VERSION 5.8 ;
BUSBITCHARS "[]" ;
DIVIDERCHAR "/" ;
UNITS
    DATABASE MICRONS 1000 ;
END UNITS

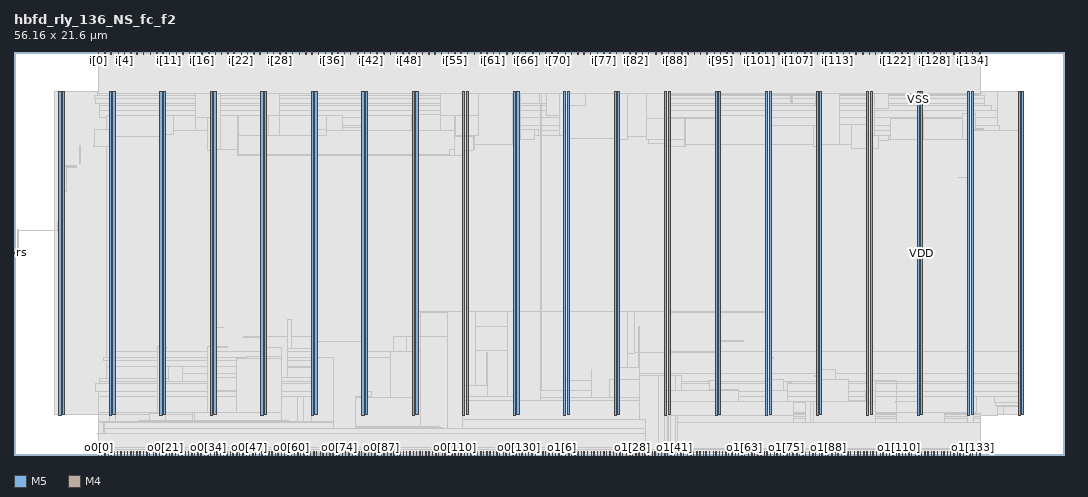
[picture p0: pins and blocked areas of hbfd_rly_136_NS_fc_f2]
MACRO hbfd_rly_136_NS_fc_f2
  FOREIGN hbfd_rly_136_NS_fc_f2 0 0 ;
  CLASS BLOCK ;
  SIZE 56.16 BY 21.6 ;
  PIN clk_in
    DIRECTION INPUT ;
    USE SIGNAL ;
    PORT
      LAYER M5 ;
        RECT  28.08 21.408 28.104 21.6 ;
    END
  END clk_in
  PIN clk_out0
    DIRECTION OUTPUT ;
    USE SIGNAL ;
    PORT
      LAYER M5 ;
        RECT  16.176 0 16.2 0.192 ;
    END
  END clk_out0
  PIN clk_out1
    DIRECTION OUTPUT ;
    USE SIGNAL ;
    PORT
      LAYER M5 ;
        RECT  39.936 0 39.96 0.192 ;
    END
  END clk_out1
  PIN i[0]
    DIRECTION INPUT ;
    USE SIGNAL ;
    PORT
      LAYER M5 ;
        RECT  4.512 21.408 4.536 21.6 ;
    END
  END i[0]
  PIN i[100]
    DIRECTION INPUT ;
    USE SIGNAL ;
    PORT
      LAYER M5 ;
        RECT  39.504 21.408 39.528 21.6 ;
    END
  END i[100]
  PIN i[101]
    DIRECTION INPUT ;
    USE SIGNAL ;
    PORT
      LAYER M5 ;
        RECT  39.84 21.408 39.864 21.6 ;
    END
  END i[101]
  PIN i[102]
    DIRECTION INPUT ;
    USE SIGNAL ;
    PORT
      LAYER M5 ;
        RECT  40.176 21.408 40.2 21.6 ;
    END
  END i[102]
  PIN i[103]
    DIRECTION INPUT ;
    USE SIGNAL ;
    PORT
      LAYER M5 ;
        RECT  40.56 21.408 40.584 21.6 ;
    END
  END i[103]
  PIN i[104]
    DIRECTION INPUT ;
    USE SIGNAL ;
    PORT
      LAYER M5 ;
        RECT  40.896 21.408 40.92 21.6 ;
    END
  END i[104]
  PIN i[105]
    DIRECTION INPUT ;
    USE SIGNAL ;
    PORT
      LAYER M5 ;
        RECT  41.232 21.408 41.256 21.6 ;
    END
  END i[105]
  PIN i[106]
    DIRECTION INPUT ;
    USE SIGNAL ;
    PORT
      LAYER M5 ;
        RECT  41.568 21.408 41.592 21.6 ;
    END
  END i[106]
  PIN i[107]
    DIRECTION INPUT ;
    USE SIGNAL ;
    PORT
      LAYER M5 ;
        RECT  41.904 21.408 41.928 21.6 ;
    END
  END i[107]
  PIN i[108]
    DIRECTION INPUT ;
    USE SIGNAL ;
    PORT
      LAYER M5 ;
        RECT  42.288 21.408 42.312 21.6 ;
    END
  END i[108]
  PIN i[109]
    DIRECTION INPUT ;
    USE SIGNAL ;
    PORT
      LAYER M5 ;
        RECT  42.624 21.408 42.648 21.6 ;
    END
  END i[109]
  PIN i[10]
    DIRECTION INPUT ;
    USE SIGNAL ;
    PORT
      LAYER M5 ;
        RECT  7.968 21.408 7.992 21.6 ;
    END
  END i[10]
  PIN i[110]
    DIRECTION INPUT ;
    USE SIGNAL ;
    PORT
      LAYER M5 ;
        RECT  42.96 21.408 42.984 21.6 ;
    END
  END i[110]
  PIN i[111]
    DIRECTION INPUT ;
    USE SIGNAL ;
    PORT
      LAYER M5 ;
        RECT  43.296 21.408 43.32 21.6 ;
    END
  END i[111]
  PIN i[112]
    DIRECTION INPUT ;
    USE SIGNAL ;
    PORT
      LAYER M5 ;
        RECT  43.68 21.408 43.704 21.6 ;
    END
  END i[112]
  PIN i[113]
    DIRECTION INPUT ;
    USE SIGNAL ;
    PORT
      LAYER M5 ;
        RECT  44.016 21.408 44.04 21.6 ;
    END
  END i[113]
  PIN i[114]
    DIRECTION INPUT ;
    USE SIGNAL ;
    PORT
      LAYER M5 ;
        RECT  44.352 21.408 44.376 21.6 ;
    END
  END i[114]
  PIN i[115]
    DIRECTION INPUT ;
    USE SIGNAL ;
    PORT
      LAYER M5 ;
        RECT  44.688 21.408 44.712 21.6 ;
    END
  END i[115]
  PIN i[116]
    DIRECTION INPUT ;
    USE SIGNAL ;
    PORT
      LAYER M5 ;
        RECT  45.024 21.408 45.048 21.6 ;
    END
  END i[116]
  PIN i[117]
    DIRECTION INPUT ;
    USE SIGNAL ;
    PORT
      LAYER M5 ;
        RECT  45.408 21.408 45.432 21.6 ;
    END
  END i[117]
  PIN i[118]
    DIRECTION INPUT ;
    USE SIGNAL ;
    PORT
      LAYER M5 ;
        RECT  45.744 21.408 45.768 21.6 ;
    END
  END i[118]
  PIN i[119]
    DIRECTION INPUT ;
    USE SIGNAL ;
    PORT
      LAYER M5 ;
        RECT  46.08 21.408 46.104 21.6 ;
    END
  END i[119]
  PIN i[11]
    DIRECTION INPUT ;
    USE SIGNAL ;
    PORT
      LAYER M5 ;
        RECT  8.304 21.408 8.328 21.6 ;
    END
  END i[11]
  PIN i[120]
    DIRECTION INPUT ;
    USE SIGNAL ;
    PORT
      LAYER M5 ;
        RECT  46.416 21.408 46.44 21.6 ;
    END
  END i[120]
  PIN i[121]
    DIRECTION INPUT ;
    USE SIGNAL ;
    PORT
      LAYER M5 ;
        RECT  46.8 21.408 46.824 21.6 ;
    END
  END i[121]
  PIN i[122]
    DIRECTION INPUT ;
    USE SIGNAL ;
    PORT
      LAYER M5 ;
        RECT  47.136 21.408 47.16 21.6 ;
    END
  END i[122]
  PIN i[123]
    DIRECTION INPUT ;
    USE SIGNAL ;
    PORT
      LAYER M5 ;
        RECT  47.472 21.408 47.496 21.6 ;
    END
  END i[123]
  PIN i[124]
    DIRECTION INPUT ;
    USE SIGNAL ;
    PORT
      LAYER M5 ;
        RECT  47.808 21.408 47.832 21.6 ;
    END
  END i[124]
  PIN i[125]
    DIRECTION INPUT ;
    USE SIGNAL ;
    PORT
      LAYER M5 ;
        RECT  48.144 21.408 48.168 21.6 ;
    END
  END i[125]
  PIN i[126]
    DIRECTION INPUT ;
    USE SIGNAL ;
    PORT
      LAYER M5 ;
        RECT  48.528 21.408 48.552 21.6 ;
    END
  END i[126]
  PIN i[127]
    DIRECTION INPUT ;
    USE SIGNAL ;
    PORT
      LAYER M5 ;
        RECT  48.864 21.408 48.888 21.6 ;
    END
  END i[127]
  PIN i[128]
    DIRECTION INPUT ;
    USE SIGNAL ;
    PORT
      LAYER M5 ;
        RECT  49.2 21.408 49.224 21.6 ;
    END
  END i[128]
  PIN i[129]
    DIRECTION INPUT ;
    USE SIGNAL ;
    PORT
      LAYER M5 ;
        RECT  49.536 21.408 49.56 21.6 ;
    END
  END i[129]
  PIN i[12]
    DIRECTION INPUT ;
    USE SIGNAL ;
    PORT
      LAYER M5 ;
        RECT  8.688 21.408 8.712 21.6 ;
    END
  END i[12]
  PIN i[130]
    DIRECTION INPUT ;
    USE SIGNAL ;
    PORT
      LAYER M5 ;
        RECT  49.872 21.408 49.896 21.6 ;
    END
  END i[130]
  PIN i[131]
    DIRECTION INPUT ;
    USE SIGNAL ;
    PORT
      LAYER M5 ;
        RECT  50.256 21.408 50.28 21.6 ;
    END
  END i[131]
  PIN i[132]
    DIRECTION INPUT ;
    USE SIGNAL ;
    PORT
      LAYER M5 ;
        RECT  50.592 21.408 50.616 21.6 ;
    END
  END i[132]
  PIN i[133]
    DIRECTION INPUT ;
    USE SIGNAL ;
    PORT
      LAYER M5 ;
        RECT  50.928 21.408 50.952 21.6 ;
    END
  END i[133]
  PIN i[134]
    DIRECTION INPUT ;
    USE SIGNAL ;
    PORT
      LAYER M5 ;
        RECT  51.264 21.408 51.288 21.6 ;
    END
  END i[134]
  PIN i[135]
    DIRECTION INPUT ;
    USE SIGNAL ;
    PORT
      LAYER M5 ;
        RECT  51.648 21.408 51.672 21.6 ;
    END
  END i[135]
  PIN i[13]
    DIRECTION INPUT ;
    USE SIGNAL ;
    PORT
      LAYER M5 ;
        RECT  9.024 21.408 9.048 21.6 ;
    END
  END i[13]
  PIN i[14]
    DIRECTION INPUT ;
    USE SIGNAL ;
    PORT
      LAYER M5 ;
        RECT  9.36 21.408 9.384 21.6 ;
    END
  END i[14]
  PIN i[15]
    DIRECTION INPUT ;
    USE SIGNAL ;
    PORT
      LAYER M5 ;
        RECT  9.696 21.408 9.72 21.6 ;
    END
  END i[15]
  PIN i[16]
    DIRECTION INPUT ;
    USE SIGNAL ;
    PORT
      LAYER M5 ;
        RECT  10.032 21.408 10.056 21.6 ;
    END
  END i[16]
  PIN i[17]
    DIRECTION INPUT ;
    USE SIGNAL ;
    PORT
      LAYER M5 ;
        RECT  10.416 21.408 10.44 21.6 ;
    END
  END i[17]
  PIN i[18]
    DIRECTION INPUT ;
    USE SIGNAL ;
    PORT
      LAYER M5 ;
        RECT  10.752 21.408 10.776 21.6 ;
    END
  END i[18]
  PIN i[19]
    DIRECTION INPUT ;
    USE SIGNAL ;
    PORT
      LAYER M5 ;
        RECT  11.088 21.408 11.112 21.6 ;
    END
  END i[19]
  PIN i[1]
    DIRECTION INPUT ;
    USE SIGNAL ;
    PORT
      LAYER M5 ;
        RECT  4.848 21.408 4.872 21.6 ;
    END
  END i[1]
  PIN i[20]
    DIRECTION INPUT ;
    USE SIGNAL ;
    PORT
      LAYER M5 ;
        RECT  11.424 21.408 11.448 21.6 ;
    END
  END i[20]
  PIN i[21]
    DIRECTION INPUT ;
    USE SIGNAL ;
    PORT
      LAYER M5 ;
        RECT  11.76 21.408 11.784 21.6 ;
    END
  END i[21]
  PIN i[22]
    DIRECTION INPUT ;
    USE SIGNAL ;
    PORT
      LAYER M5 ;
        RECT  12.144 21.408 12.168 21.6 ;
    END
  END i[22]
  PIN i[23]
    DIRECTION INPUT ;
    USE SIGNAL ;
    PORT
      LAYER M5 ;
        RECT  12.48 21.408 12.504 21.6 ;
    END
  END i[23]
  PIN i[24]
    DIRECTION INPUT ;
    USE SIGNAL ;
    PORT
      LAYER M5 ;
        RECT  12.816 21.408 12.84 21.6 ;
    END
  END i[24]
  PIN i[25]
    DIRECTION INPUT ;
    USE SIGNAL ;
    PORT
      LAYER M5 ;
        RECT  13.152 21.408 13.176 21.6 ;
    END
  END i[25]
  PIN i[26]
    DIRECTION INPUT ;
    USE SIGNAL ;
    PORT
      LAYER M5 ;
        RECT  13.536 21.408 13.56 21.6 ;
    END
  END i[26]
  PIN i[27]
    DIRECTION INPUT ;
    USE SIGNAL ;
    PORT
      LAYER M5 ;
        RECT  13.872 21.408 13.896 21.6 ;
    END
  END i[27]
  PIN i[28]
    DIRECTION INPUT ;
    USE SIGNAL ;
    PORT
      LAYER M5 ;
        RECT  14.208 21.408 14.232 21.6 ;
    END
  END i[28]
  PIN i[29]
    DIRECTION INPUT ;
    USE SIGNAL ;
    PORT
      LAYER M5 ;
        RECT  14.544 21.408 14.568 21.6 ;
    END
  END i[29]
  PIN i[2]
    DIRECTION INPUT ;
    USE SIGNAL ;
    PORT
      LAYER M5 ;
        RECT  5.184 21.408 5.208 21.6 ;
    END
  END i[2]
  PIN i[30]
    DIRECTION INPUT ;
    USE SIGNAL ;
    PORT
      LAYER M5 ;
        RECT  14.88 21.408 14.904 21.6 ;
    END
  END i[30]
  PIN i[31]
    DIRECTION INPUT ;
    USE SIGNAL ;
    PORT
      LAYER M5 ;
        RECT  15.264 21.408 15.288 21.6 ;
    END
  END i[31]
  PIN i[32]
    DIRECTION INPUT ;
    USE SIGNAL ;
    PORT
      LAYER M5 ;
        RECT  15.6 21.408 15.624 21.6 ;
    END
  END i[32]
  PIN i[33]
    DIRECTION INPUT ;
    USE SIGNAL ;
    PORT
      LAYER M5 ;
        RECT  15.936 21.408 15.96 21.6 ;
    END
  END i[33]
  PIN i[34]
    DIRECTION INPUT ;
    USE SIGNAL ;
    PORT
      LAYER M5 ;
        RECT  16.272 21.408 16.296 21.6 ;
    END
  END i[34]
  PIN i[35]
    DIRECTION INPUT ;
    USE SIGNAL ;
    PORT
      LAYER M5 ;
        RECT  16.656 21.408 16.68 21.6 ;
    END
  END i[35]
  PIN i[36]
    DIRECTION INPUT ;
    USE SIGNAL ;
    PORT
      LAYER M5 ;
        RECT  16.992 21.408 17.016 21.6 ;
    END
  END i[36]
  PIN i[37]
    DIRECTION INPUT ;
    USE SIGNAL ;
    PORT
      LAYER M5 ;
        RECT  17.328 21.408 17.352 21.6 ;
    END
  END i[37]
  PIN i[38]
    DIRECTION INPUT ;
    USE SIGNAL ;
    PORT
      LAYER M5 ;
        RECT  17.664 21.408 17.688 21.6 ;
    END
  END i[38]
  PIN i[39]
    DIRECTION INPUT ;
    USE SIGNAL ;
    PORT
      LAYER M5 ;
        RECT  18 21.408 18.024 21.6 ;
    END
  END i[39]
  PIN i[3]
    DIRECTION INPUT ;
    USE SIGNAL ;
    PORT
      LAYER M5 ;
        RECT  5.568 21.408 5.592 21.6 ;
    END
  END i[3]
  PIN i[40]
    DIRECTION INPUT ;
    USE SIGNAL ;
    PORT
      LAYER M5 ;
        RECT  18.384 21.408 18.408 21.6 ;
    END
  END i[40]
  PIN i[41]
    DIRECTION INPUT ;
    USE SIGNAL ;
    PORT
      LAYER M5 ;
        RECT  18.72 21.408 18.744 21.6 ;
    END
  END i[41]
  PIN i[42]
    DIRECTION INPUT ;
    USE SIGNAL ;
    PORT
      LAYER M5 ;
        RECT  19.056 21.408 19.08 21.6 ;
    END
  END i[42]
  PIN i[43]
    DIRECTION INPUT ;
    USE SIGNAL ;
    PORT
      LAYER M5 ;
        RECT  19.392 21.408 19.416 21.6 ;
    END
  END i[43]
  PIN i[44]
    DIRECTION INPUT ;
    USE SIGNAL ;
    PORT
      LAYER M5 ;
        RECT  19.776 21.408 19.8 21.6 ;
    END
  END i[44]
  PIN i[45]
    DIRECTION INPUT ;
    USE SIGNAL ;
    PORT
      LAYER M5 ;
        RECT  20.112 21.408 20.136 21.6 ;
    END
  END i[45]
  PIN i[46]
    DIRECTION INPUT ;
    USE SIGNAL ;
    PORT
      LAYER M5 ;
        RECT  20.448 21.408 20.472 21.6 ;
    END
  END i[46]
  PIN i[47]
    DIRECTION INPUT ;
    USE SIGNAL ;
    PORT
      LAYER M5 ;
        RECT  20.784 21.408 20.808 21.6 ;
    END
  END i[47]
  PIN i[48]
    DIRECTION INPUT ;
    USE SIGNAL ;
    PORT
      LAYER M5 ;
        RECT  21.12 21.408 21.144 21.6 ;
    END
  END i[48]
  PIN i[49]
    DIRECTION INPUT ;
    USE SIGNAL ;
    PORT
      LAYER M5 ;
        RECT  21.504 21.408 21.528 21.6 ;
    END
  END i[49]
  PIN i[4]
    DIRECTION INPUT ;
    USE SIGNAL ;
    PORT
      LAYER M5 ;
        RECT  5.904 21.408 5.928 21.6 ;
    END
  END i[4]
  PIN i[50]
    DIRECTION INPUT ;
    USE SIGNAL ;
    PORT
      LAYER M5 ;
        RECT  21.84 21.408 21.864 21.6 ;
    END
  END i[50]
  PIN i[51]
    DIRECTION INPUT ;
    USE SIGNAL ;
    PORT
      LAYER M5 ;
        RECT  22.176 21.408 22.2 21.6 ;
    END
  END i[51]
  PIN i[52]
    DIRECTION INPUT ;
    USE SIGNAL ;
    PORT
      LAYER M5 ;
        RECT  22.512 21.408 22.536 21.6 ;
    END
  END i[52]
  PIN i[53]
    DIRECTION INPUT ;
    USE SIGNAL ;
    PORT
      LAYER M5 ;
        RECT  22.848 21.408 22.872 21.6 ;
    END
  END i[53]
  PIN i[54]
    DIRECTION INPUT ;
    USE SIGNAL ;
    PORT
      LAYER M5 ;
        RECT  23.232 21.408 23.256 21.6 ;
    END
  END i[54]
  PIN i[55]
    DIRECTION INPUT ;
    USE SIGNAL ;
    PORT
      LAYER M5 ;
        RECT  23.568 21.408 23.592 21.6 ;
    END
  END i[55]
  PIN i[56]
    DIRECTION INPUT ;
    USE SIGNAL ;
    PORT
      LAYER M5 ;
        RECT  23.904 21.408 23.928 21.6 ;
    END
  END i[56]
  PIN i[57]
    DIRECTION INPUT ;
    USE SIGNAL ;
    PORT
      LAYER M5 ;
        RECT  24.24 21.408 24.264 21.6 ;
    END
  END i[57]
  PIN i[58]
    DIRECTION INPUT ;
    USE SIGNAL ;
    PORT
      LAYER M5 ;
        RECT  24.624 21.408 24.648 21.6 ;
    END
  END i[58]
  PIN i[59]
    DIRECTION INPUT ;
    USE SIGNAL ;
    PORT
      LAYER M5 ;
        RECT  24.96 21.408 24.984 21.6 ;
    END
  END i[59]
  PIN i[5]
    DIRECTION INPUT ;
    USE SIGNAL ;
    PORT
      LAYER M5 ;
        RECT  6.24 21.408 6.264 21.6 ;
    END
  END i[5]
  PIN i[60]
    DIRECTION INPUT ;
    USE SIGNAL ;
    PORT
      LAYER M5 ;
        RECT  25.296 21.408 25.32 21.6 ;
    END
  END i[60]
  PIN i[61]
    DIRECTION INPUT ;
    USE SIGNAL ;
    PORT
      LAYER M5 ;
        RECT  25.632 21.408 25.656 21.6 ;
    END
  END i[61]
  PIN i[62]
    DIRECTION INPUT ;
    USE SIGNAL ;
    PORT
      LAYER M5 ;
        RECT  25.968 21.408 25.992 21.6 ;
    END
  END i[62]
  PIN i[63]
    DIRECTION INPUT ;
    USE SIGNAL ;
    PORT
      LAYER M5 ;
        RECT  26.352 21.408 26.376 21.6 ;
    END
  END i[63]
  PIN i[64]
    DIRECTION INPUT ;
    USE SIGNAL ;
    PORT
      LAYER M5 ;
        RECT  26.688 21.408 26.712 21.6 ;
    END
  END i[64]
  PIN i[65]
    DIRECTION INPUT ;
    USE SIGNAL ;
    PORT
      LAYER M5 ;
        RECT  27.024 21.408 27.048 21.6 ;
    END
  END i[65]
  PIN i[66]
    DIRECTION INPUT ;
    USE SIGNAL ;
    PORT
      LAYER M5 ;
        RECT  27.36 21.408 27.384 21.6 ;
    END
  END i[66]
  PIN i[67]
    DIRECTION INPUT ;
    USE SIGNAL ;
    PORT
      LAYER M5 ;
        RECT  27.744 21.408 27.768 21.6 ;
    END
  END i[67]
  PIN i[68]
    DIRECTION INPUT ;
    USE SIGNAL ;
    PORT
      LAYER M5 ;
        RECT  28.416 21.408 28.44 21.6 ;
    END
  END i[68]
  PIN i[69]
    DIRECTION INPUT ;
    USE SIGNAL ;
    PORT
      LAYER M5 ;
        RECT  28.752 21.408 28.776 21.6 ;
    END
  END i[69]
  PIN i[6]
    DIRECTION INPUT ;
    USE SIGNAL ;
    PORT
      LAYER M5 ;
        RECT  6.576 21.408 6.6 21.6 ;
    END
  END i[6]
  PIN i[70]
    DIRECTION INPUT ;
    USE SIGNAL ;
    PORT
      LAYER M5 ;
        RECT  29.088 21.408 29.112 21.6 ;
    END
  END i[70]
  PIN i[71]
    DIRECTION INPUT ;
    USE SIGNAL ;
    PORT
      LAYER M5 ;
        RECT  29.472 21.408 29.496 21.6 ;
    END
  END i[71]
  PIN i[72]
    DIRECTION INPUT ;
    USE SIGNAL ;
    PORT
      LAYER M5 ;
        RECT  29.808 21.408 29.832 21.6 ;
    END
  END i[72]
  PIN i[73]
    DIRECTION INPUT ;
    USE SIGNAL ;
    PORT
      LAYER M5 ;
        RECT  30.144 21.408 30.168 21.6 ;
    END
  END i[73]
  PIN i[74]
    DIRECTION INPUT ;
    USE SIGNAL ;
    PORT
      LAYER M5 ;
        RECT  30.48 21.408 30.504 21.6 ;
    END
  END i[74]
  PIN i[75]
    DIRECTION INPUT ;
    USE SIGNAL ;
    PORT
      LAYER M5 ;
        RECT  30.816 21.408 30.84 21.6 ;
    END
  END i[75]
  PIN i[76]
    DIRECTION INPUT ;
    USE SIGNAL ;
    PORT
      LAYER M5 ;
        RECT  31.2 21.408 31.224 21.6 ;
    END
  END i[76]
  PIN i[77]
    DIRECTION INPUT ;
    USE SIGNAL ;
    PORT
      LAYER M5 ;
        RECT  31.536 21.408 31.56 21.6 ;
    END
  END i[77]
  PIN i[78]
    DIRECTION INPUT ;
    USE SIGNAL ;
    PORT
      LAYER M5 ;
        RECT  31.872 21.408 31.896 21.6 ;
    END
  END i[78]
  PIN i[79]
    DIRECTION INPUT ;
    USE SIGNAL ;
    PORT
      LAYER M5 ;
        RECT  32.208 21.408 32.232 21.6 ;
    END
  END i[79]
  PIN i[7]
    DIRECTION INPUT ;
    USE SIGNAL ;
    PORT
      LAYER M5 ;
        RECT  6.912 21.408 6.936 21.6 ;
    END
  END i[7]
  PIN i[80]
    DIRECTION INPUT ;
    USE SIGNAL ;
    PORT
      LAYER M5 ;
        RECT  32.592 21.408 32.616 21.6 ;
    END
  END i[80]
  PIN i[81]
    DIRECTION INPUT ;
    USE SIGNAL ;
    PORT
      LAYER M5 ;
        RECT  32.928 21.408 32.952 21.6 ;
    END
  END i[81]
  PIN i[82]
    DIRECTION INPUT ;
    USE SIGNAL ;
    PORT
      LAYER M5 ;
        RECT  33.264 21.408 33.288 21.6 ;
    END
  END i[82]
  PIN i[83]
    DIRECTION INPUT ;
    USE SIGNAL ;
    PORT
      LAYER M5 ;
        RECT  33.6 21.408 33.624 21.6 ;
    END
  END i[83]
  PIN i[84]
    DIRECTION INPUT ;
    USE SIGNAL ;
    PORT
      LAYER M5 ;
        RECT  33.936 21.408 33.96 21.6 ;
    END
  END i[84]
  PIN i[85]
    DIRECTION INPUT ;
    USE SIGNAL ;
    PORT
      LAYER M5 ;
        RECT  34.32 21.408 34.344 21.6 ;
    END
  END i[85]
  PIN i[86]
    DIRECTION INPUT ;
    USE SIGNAL ;
    PORT
      LAYER M5 ;
        RECT  34.656 21.408 34.68 21.6 ;
    END
  END i[86]
  PIN i[87]
    DIRECTION INPUT ;
    USE SIGNAL ;
    PORT
      LAYER M5 ;
        RECT  34.992 21.408 35.016 21.6 ;
    END
  END i[87]
  PIN i[88]
    DIRECTION INPUT ;
    USE SIGNAL ;
    PORT
      LAYER M5 ;
        RECT  35.328 21.408 35.352 21.6 ;
    END
  END i[88]
  PIN i[89]
    DIRECTION INPUT ;
    USE SIGNAL ;
    PORT
      LAYER M5 ;
        RECT  35.712 21.408 35.736 21.6 ;
    END
  END i[89]
  PIN i[8]
    DIRECTION INPUT ;
    USE SIGNAL ;
    PORT
      LAYER M5 ;
        RECT  7.296 21.408 7.32 21.6 ;
    END
  END i[8]
  PIN i[90]
    DIRECTION INPUT ;
    USE SIGNAL ;
    PORT
      LAYER M5 ;
        RECT  36.048 21.408 36.072 21.6 ;
    END
  END i[90]
  PIN i[91]
    DIRECTION INPUT ;
    USE SIGNAL ;
    PORT
      LAYER M5 ;
        RECT  36.384 21.408 36.408 21.6 ;
    END
  END i[91]
  PIN i[92]
    DIRECTION INPUT ;
    USE SIGNAL ;
    PORT
      LAYER M5 ;
        RECT  36.72 21.408 36.744 21.6 ;
    END
  END i[92]
  PIN i[93]
    DIRECTION INPUT ;
    USE SIGNAL ;
    PORT
      LAYER M5 ;
        RECT  37.056 21.408 37.08 21.6 ;
    END
  END i[93]
  PIN i[94]
    DIRECTION INPUT ;
    USE SIGNAL ;
    PORT
      LAYER M5 ;
        RECT  37.44 21.408 37.464 21.6 ;
    END
  END i[94]
  PIN i[95]
    DIRECTION INPUT ;
    USE SIGNAL ;
    PORT
      LAYER M5 ;
        RECT  37.776 21.408 37.8 21.6 ;
    END
  END i[95]
  PIN i[96]
    DIRECTION INPUT ;
    USE SIGNAL ;
    PORT
      LAYER M5 ;
        RECT  38.112 21.408 38.136 21.6 ;
    END
  END i[96]
  PIN i[97]
    DIRECTION INPUT ;
    USE SIGNAL ;
    PORT
      LAYER M5 ;
        RECT  38.448 21.408 38.472 21.6 ;
    END
  END i[97]
  PIN i[98]
    DIRECTION INPUT ;
    USE SIGNAL ;
    PORT
      LAYER M5 ;
        RECT  38.832 21.408 38.856 21.6 ;
    END
  END i[98]
  PIN i[99]
    DIRECTION INPUT ;
    USE SIGNAL ;
    PORT
      LAYER M5 ;
        RECT  39.168 21.408 39.192 21.6 ;
    END
  END i[99]
  PIN i[9]
    DIRECTION INPUT ;
    USE SIGNAL ;
    PORT
      LAYER M5 ;
        RECT  7.632 21.408 7.656 21.6 ;
    END
  END i[9]
  PIN o0[0]
    DIRECTION OUTPUT ;
    USE SIGNAL ;
    PORT
      LAYER M5 ;
        RECT  4.512 0 4.536 0.192 ;
    END
  END o0[0]
  PIN o0[100]
    DIRECTION OUTPUT ;
    USE SIGNAL ;
    PORT
      LAYER M5 ;
        RECT  21.84 0 21.864 0.192 ;
    END
  END o0[100]
  PIN o0[101]
    DIRECTION OUTPUT ;
    USE SIGNAL ;
    PORT
      LAYER M5 ;
        RECT  22.032 0 22.056 0.192 ;
    END
  END o0[101]
  PIN o0[102]
    DIRECTION OUTPUT ;
    USE SIGNAL ;
    PORT
      LAYER M5 ;
        RECT  22.176 0 22.2 0.192 ;
    END
  END o0[102]
  PIN o0[103]
    DIRECTION OUTPUT ;
    USE SIGNAL ;
    PORT
      LAYER M5 ;
        RECT  22.368 0 22.392 0.192 ;
    END
  END o0[103]
  PIN o0[104]
    DIRECTION OUTPUT ;
    USE SIGNAL ;
    PORT
      LAYER M5 ;
        RECT  22.56 0 22.584 0.192 ;
    END
  END o0[104]
  PIN o0[105]
    DIRECTION OUTPUT ;
    USE SIGNAL ;
    PORT
      LAYER M5 ;
        RECT  22.704 0 22.728 0.192 ;
    END
  END o0[105]
  PIN o0[106]
    DIRECTION OUTPUT ;
    USE SIGNAL ;
    PORT
      LAYER M5 ;
        RECT  22.896 0 22.92 0.192 ;
    END
  END o0[106]
  PIN o0[107]
    DIRECTION OUTPUT ;
    USE SIGNAL ;
    PORT
      LAYER M5 ;
        RECT  23.04 0 23.064 0.192 ;
    END
  END o0[107]
  PIN o0[108]
    DIRECTION OUTPUT ;
    USE SIGNAL ;
    PORT
      LAYER M5 ;
        RECT  23.232 0 23.256 0.192 ;
    END
  END o0[108]
  PIN o0[109]
    DIRECTION OUTPUT ;
    USE SIGNAL ;
    PORT
      LAYER M5 ;
        RECT  23.424 0 23.448 0.192 ;
    END
  END o0[109]
  PIN o0[10]
    DIRECTION OUTPUT ;
    USE SIGNAL ;
    PORT
      LAYER M5 ;
        RECT  6.24 0 6.264 0.192 ;
    END
  END o0[10]
  PIN o0[110]
    DIRECTION OUTPUT ;
    USE SIGNAL ;
    PORT
      LAYER M5 ;
        RECT  23.568 0 23.592 0.192 ;
    END
  END o0[110]
  PIN o0[111]
    DIRECTION OUTPUT ;
    USE SIGNAL ;
    PORT
      LAYER M5 ;
        RECT  23.76 0 23.784 0.192 ;
    END
  END o0[111]
  PIN o0[112]
    DIRECTION OUTPUT ;
    USE SIGNAL ;
    PORT
      LAYER M5 ;
        RECT  23.904 0 23.928 0.192 ;
    END
  END o0[112]
  PIN o0[113]
    DIRECTION OUTPUT ;
    USE SIGNAL ;
    PORT
      LAYER M5 ;
        RECT  24.096 0 24.12 0.192 ;
    END
  END o0[113]
  PIN o0[114]
    DIRECTION OUTPUT ;
    USE SIGNAL ;
    PORT
      LAYER M5 ;
        RECT  24.24 0 24.264 0.192 ;
    END
  END o0[114]
  PIN o0[115]
    DIRECTION OUTPUT ;
    USE SIGNAL ;
    PORT
      LAYER M5 ;
        RECT  24.432 0 24.456 0.192 ;
    END
  END o0[115]
  PIN o0[116]
    DIRECTION OUTPUT ;
    USE SIGNAL ;
    PORT
      LAYER M5 ;
        RECT  24.624 0 24.648 0.192 ;
    END
  END o0[116]
  PIN o0[117]
    DIRECTION OUTPUT ;
    USE SIGNAL ;
    PORT
      LAYER M5 ;
        RECT  24.768 0 24.792 0.192 ;
    END
  END o0[117]
  PIN o0[118]
    DIRECTION OUTPUT ;
    USE SIGNAL ;
    PORT
      LAYER M5 ;
        RECT  24.96 0 24.984 0.192 ;
    END
  END o0[118]
  PIN o0[119]
    DIRECTION OUTPUT ;
    USE SIGNAL ;
    PORT
      LAYER M5 ;
        RECT  25.104 0 25.128 0.192 ;
    END
  END o0[119]
  PIN o0[11]
    DIRECTION OUTPUT ;
    USE SIGNAL ;
    PORT
      LAYER M5 ;
        RECT  6.384 0 6.408 0.192 ;
    END
  END o0[11]
  PIN o0[120]
    DIRECTION OUTPUT ;
    USE SIGNAL ;
    PORT
      LAYER M5 ;
        RECT  25.296 0 25.32 0.192 ;
    END
  END o0[120]
  PIN o0[121]
    DIRECTION OUTPUT ;
    USE SIGNAL ;
    PORT
      LAYER M5 ;
        RECT  25.44 0 25.464 0.192 ;
    END
  END o0[121]
  PIN o0[122]
    DIRECTION OUTPUT ;
    USE SIGNAL ;
    PORT
      LAYER M5 ;
        RECT  25.632 0 25.656 0.192 ;
    END
  END o0[122]
  PIN o0[123]
    DIRECTION OUTPUT ;
    USE SIGNAL ;
    PORT
      LAYER M5 ;
        RECT  25.824 0 25.848 0.192 ;
    END
  END o0[123]
  PIN o0[124]
    DIRECTION OUTPUT ;
    USE SIGNAL ;
    PORT
      LAYER M5 ;
        RECT  25.968 0 25.992 0.192 ;
    END
  END o0[124]
  PIN o0[125]
    DIRECTION OUTPUT ;
    USE SIGNAL ;
    PORT
      LAYER M5 ;
        RECT  26.16 0 26.184 0.192 ;
    END
  END o0[125]
  PIN o0[126]
    DIRECTION OUTPUT ;
    USE SIGNAL ;
    PORT
      LAYER M5 ;
        RECT  26.304 0 26.328 0.192 ;
    END
  END o0[126]
  PIN o0[127]
    DIRECTION OUTPUT ;
    USE SIGNAL ;
    PORT
      LAYER M5 ;
        RECT  26.496 0 26.52 0.192 ;
    END
  END o0[127]
  PIN o0[128]
    DIRECTION OUTPUT ;
    USE SIGNAL ;
    PORT
      LAYER M5 ;
        RECT  26.688 0 26.712 0.192 ;
    END
  END o0[128]
  PIN o0[129]
    DIRECTION OUTPUT ;
    USE SIGNAL ;
    PORT
      LAYER M5 ;
        RECT  26.832 0 26.856 0.192 ;
    END
  END o0[129]
  PIN o0[12]
    DIRECTION OUTPUT ;
    USE SIGNAL ;
    PORT
      LAYER M5 ;
        RECT  6.576 0 6.6 0.192 ;
    END
  END o0[12]
  PIN o0[130]
    DIRECTION OUTPUT ;
    USE SIGNAL ;
    PORT
      LAYER M5 ;
        RECT  27.024 0 27.048 0.192 ;
    END
  END o0[130]
  PIN o0[131]
    DIRECTION OUTPUT ;
    USE SIGNAL ;
    PORT
      LAYER M5 ;
        RECT  27.168 0 27.192 0.192 ;
    END
  END o0[131]
  PIN o0[132]
    DIRECTION OUTPUT ;
    USE SIGNAL ;
    PORT
      LAYER M5 ;
        RECT  27.36 0 27.384 0.192 ;
    END
  END o0[132]
  PIN o0[133]
    DIRECTION OUTPUT ;
    USE SIGNAL ;
    PORT
      LAYER M5 ;
        RECT  27.504 0 27.528 0.192 ;
    END
  END o0[133]
  PIN o0[134]
    DIRECTION OUTPUT ;
    USE SIGNAL ;
    PORT
      LAYER M5 ;
        RECT  27.696 0 27.72 0.192 ;
    END
  END o0[134]
  PIN o0[135]
    DIRECTION OUTPUT ;
    USE SIGNAL ;
    PORT
      LAYER M5 ;
        RECT  27.888 0 27.912 0.192 ;
    END
  END o0[135]
  PIN o0[13]
    DIRECTION OUTPUT ;
    USE SIGNAL ;
    PORT
      LAYER M5 ;
        RECT  6.72 0 6.744 0.192 ;
    END
  END o0[13]
  PIN o0[14]
    DIRECTION OUTPUT ;
    USE SIGNAL ;
    PORT
      LAYER M5 ;
        RECT  6.912 0 6.936 0.192 ;
    END
  END o0[14]
  PIN o0[15]
    DIRECTION OUTPUT ;
    USE SIGNAL ;
    PORT
      LAYER M5 ;
        RECT  7.104 0 7.128 0.192 ;
    END
  END o0[15]
  PIN o0[16]
    DIRECTION OUTPUT ;
    USE SIGNAL ;
    PORT
      LAYER M5 ;
        RECT  7.248 0 7.272 0.192 ;
    END
  END o0[16]
  PIN o0[17]
    DIRECTION OUTPUT ;
    USE SIGNAL ;
    PORT
      LAYER M5 ;
        RECT  7.44 0 7.464 0.192 ;
    END
  END o0[17]
  PIN o0[18]
    DIRECTION OUTPUT ;
    USE SIGNAL ;
    PORT
      LAYER M5 ;
        RECT  7.584 0 7.608 0.192 ;
    END
  END o0[18]
  PIN o0[19]
    DIRECTION OUTPUT ;
    USE SIGNAL ;
    PORT
      LAYER M5 ;
        RECT  7.776 0 7.8 0.192 ;
    END
  END o0[19]
  PIN o0[1]
    DIRECTION OUTPUT ;
    USE SIGNAL ;
    PORT
      LAYER M5 ;
        RECT  4.656 0 4.68 0.192 ;
    END
  END o0[1]
  PIN o0[20]
    DIRECTION OUTPUT ;
    USE SIGNAL ;
    PORT
      LAYER M5 ;
        RECT  7.92 0 7.944 0.192 ;
    END
  END o0[20]
  PIN o0[21]
    DIRECTION OUTPUT ;
    USE SIGNAL ;
    PORT
      LAYER M5 ;
        RECT  8.112 0 8.136 0.192 ;
    END
  END o0[21]
  PIN o0[22]
    DIRECTION OUTPUT ;
    USE SIGNAL ;
    PORT
      LAYER M5 ;
        RECT  8.304 0 8.328 0.192 ;
    END
  END o0[22]
  PIN o0[23]
    DIRECTION OUTPUT ;
    USE SIGNAL ;
    PORT
      LAYER M5 ;
        RECT  8.448 0 8.472 0.192 ;
    END
  END o0[23]
  PIN o0[24]
    DIRECTION OUTPUT ;
    USE SIGNAL ;
    PORT
      LAYER M5 ;
        RECT  8.64 0 8.664 0.192 ;
    END
  END o0[24]
  PIN o0[25]
    DIRECTION OUTPUT ;
    USE SIGNAL ;
    PORT
      LAYER M5 ;
        RECT  8.784 0 8.808 0.192 ;
    END
  END o0[25]
  PIN o0[26]
    DIRECTION OUTPUT ;
    USE SIGNAL ;
    PORT
      LAYER M5 ;
        RECT  8.976 0 9 0.192 ;
    END
  END o0[26]
  PIN o0[27]
    DIRECTION OUTPUT ;
    USE SIGNAL ;
    PORT
      LAYER M5 ;
        RECT  9.168 0 9.192 0.192 ;
    END
  END o0[27]
  PIN o0[28]
    DIRECTION OUTPUT ;
    USE SIGNAL ;
    PORT
      LAYER M5 ;
        RECT  9.312 0 9.336 0.192 ;
    END
  END o0[28]
  PIN o0[29]
    DIRECTION OUTPUT ;
    USE SIGNAL ;
    PORT
      LAYER M5 ;
        RECT  9.504 0 9.528 0.192 ;
    END
  END o0[29]
  PIN o0[2]
    DIRECTION OUTPUT ;
    USE SIGNAL ;
    PORT
      LAYER M5 ;
        RECT  4.848 0 4.872 0.192 ;
    END
  END o0[2]
  PIN o0[30]
    DIRECTION OUTPUT ;
    USE SIGNAL ;
    PORT
      LAYER M5 ;
        RECT  9.648 0 9.672 0.192 ;
    END
  END o0[30]
  PIN o0[31]
    DIRECTION OUTPUT ;
    USE SIGNAL ;
    PORT
      LAYER M5 ;
        RECT  9.84 0 9.864 0.192 ;
    END
  END o0[31]
  PIN o0[32]
    DIRECTION OUTPUT ;
    USE SIGNAL ;
    PORT
      LAYER M5 ;
        RECT  9.984 0 10.008 0.192 ;
    END
  END o0[32]
  PIN o0[33]
    DIRECTION OUTPUT ;
    USE SIGNAL ;
    PORT
      LAYER M5 ;
        RECT  10.176 0 10.2 0.192 ;
    END
  END o0[33]
  PIN o0[34]
    DIRECTION OUTPUT ;
    USE SIGNAL ;
    PORT
      LAYER M5 ;
        RECT  10.368 0 10.392 0.192 ;
    END
  END o0[34]
  PIN o0[35]
    DIRECTION OUTPUT ;
    USE SIGNAL ;
    PORT
      LAYER M5 ;
        RECT  10.512 0 10.536 0.192 ;
    END
  END o0[35]
  PIN o0[36]
    DIRECTION OUTPUT ;
    USE SIGNAL ;
    PORT
      LAYER M5 ;
        RECT  10.704 0 10.728 0.192 ;
    END
  END o0[36]
  PIN o0[37]
    DIRECTION OUTPUT ;
    USE SIGNAL ;
    PORT
      LAYER M5 ;
        RECT  10.848 0 10.872 0.192 ;
    END
  END o0[37]
  PIN o0[38]
    DIRECTION OUTPUT ;
    USE SIGNAL ;
    PORT
      LAYER M5 ;
        RECT  11.04 0 11.064 0.192 ;
    END
  END o0[38]
  PIN o0[39]
    DIRECTION OUTPUT ;
    USE SIGNAL ;
    PORT
      LAYER M5 ;
        RECT  11.184 0 11.208 0.192 ;
    END
  END o0[39]
  PIN o0[3]
    DIRECTION OUTPUT ;
    USE SIGNAL ;
    PORT
      LAYER M5 ;
        RECT  5.04 0 5.064 0.192 ;
    END
  END o0[3]
  PIN o0[40]
    DIRECTION OUTPUT ;
    USE SIGNAL ;
    PORT
      LAYER M5 ;
        RECT  11.376 0 11.4 0.192 ;
    END
  END o0[40]
  PIN o0[41]
    DIRECTION OUTPUT ;
    USE SIGNAL ;
    PORT
      LAYER M5 ;
        RECT  11.568 0 11.592 0.192 ;
    END
  END o0[41]
  PIN o0[42]
    DIRECTION OUTPUT ;
    USE SIGNAL ;
    PORT
      LAYER M5 ;
        RECT  11.712 0 11.736 0.192 ;
    END
  END o0[42]
  PIN o0[43]
    DIRECTION OUTPUT ;
    USE SIGNAL ;
    PORT
      LAYER M5 ;
        RECT  11.904 0 11.928 0.192 ;
    END
  END o0[43]
  PIN o0[44]
    DIRECTION OUTPUT ;
    USE SIGNAL ;
    PORT
      LAYER M5 ;
        RECT  12.048 0 12.072 0.192 ;
    END
  END o0[44]
  PIN o0[45]
    DIRECTION OUTPUT ;
    USE SIGNAL ;
    PORT
      LAYER M5 ;
        RECT  12.24 0 12.264 0.192 ;
    END
  END o0[45]
  PIN o0[46]
    DIRECTION OUTPUT ;
    USE SIGNAL ;
    PORT
      LAYER M5 ;
        RECT  12.432 0 12.456 0.192 ;
    END
  END o0[46]
  PIN o0[47]
    DIRECTION OUTPUT ;
    USE SIGNAL ;
    PORT
      LAYER M5 ;
        RECT  12.576 0 12.6 0.192 ;
    END
  END o0[47]
  PIN o0[48]
    DIRECTION OUTPUT ;
    USE SIGNAL ;
    PORT
      LAYER M5 ;
        RECT  12.768 0 12.792 0.192 ;
    END
  END o0[48]
  PIN o0[49]
    DIRECTION OUTPUT ;
    USE SIGNAL ;
    PORT
      LAYER M5 ;
        RECT  12.912 0 12.936 0.192 ;
    END
  END o0[49]
  PIN o0[4]
    DIRECTION OUTPUT ;
    USE SIGNAL ;
    PORT
      LAYER M5 ;
        RECT  5.184 0 5.208 0.192 ;
    END
  END o0[4]
  PIN o0[50]
    DIRECTION OUTPUT ;
    USE SIGNAL ;
    PORT
      LAYER M5 ;
        RECT  13.104 0 13.128 0.192 ;
    END
  END o0[50]
  PIN o0[51]
    DIRECTION OUTPUT ;
    USE SIGNAL ;
    PORT
      LAYER M5 ;
        RECT  13.248 0 13.272 0.192 ;
    END
  END o0[51]
  PIN o0[52]
    DIRECTION OUTPUT ;
    USE SIGNAL ;
    PORT
      LAYER M5 ;
        RECT  13.44 0 13.464 0.192 ;
    END
  END o0[52]
  PIN o0[53]
    DIRECTION OUTPUT ;
    USE SIGNAL ;
    PORT
      LAYER M5 ;
        RECT  13.632 0 13.656 0.192 ;
    END
  END o0[53]
  PIN o0[54]
    DIRECTION OUTPUT ;
    USE SIGNAL ;
    PORT
      LAYER M5 ;
        RECT  13.776 0 13.8 0.192 ;
    END
  END o0[54]
  PIN o0[55]
    DIRECTION OUTPUT ;
    USE SIGNAL ;
    PORT
      LAYER M5 ;
        RECT  13.968 0 13.992 0.192 ;
    END
  END o0[55]
  PIN o0[56]
    DIRECTION OUTPUT ;
    USE SIGNAL ;
    PORT
      LAYER M5 ;
        RECT  14.112 0 14.136 0.192 ;
    END
  END o0[56]
  PIN o0[57]
    DIRECTION OUTPUT ;
    USE SIGNAL ;
    PORT
      LAYER M5 ;
        RECT  14.304 0 14.328 0.192 ;
    END
  END o0[57]
  PIN o0[58]
    DIRECTION OUTPUT ;
    USE SIGNAL ;
    PORT
      LAYER M5 ;
        RECT  14.448 0 14.472 0.192 ;
    END
  END o0[58]
  PIN o0[59]
    DIRECTION OUTPUT ;
    USE SIGNAL ;
    PORT
      LAYER M5 ;
        RECT  14.64 0 14.664 0.192 ;
    END
  END o0[59]
  PIN o0[5]
    DIRECTION OUTPUT ;
    USE SIGNAL ;
    PORT
      LAYER M5 ;
        RECT  5.376 0 5.4 0.192 ;
    END
  END o0[5]
  PIN o0[60]
    DIRECTION OUTPUT ;
    USE SIGNAL ;
    PORT
      LAYER M5 ;
        RECT  14.832 0 14.856 0.192 ;
    END
  END o0[60]
  PIN o0[61]
    DIRECTION OUTPUT ;
    USE SIGNAL ;
    PORT
      LAYER M5 ;
        RECT  14.976 0 15 0.192 ;
    END
  END o0[61]
  PIN o0[62]
    DIRECTION OUTPUT ;
    USE SIGNAL ;
    PORT
      LAYER M5 ;
        RECT  15.168 0 15.192 0.192 ;
    END
  END o0[62]
  PIN o0[63]
    DIRECTION OUTPUT ;
    USE SIGNAL ;
    PORT
      LAYER M5 ;
        RECT  15.312 0 15.336 0.192 ;
    END
  END o0[63]
  PIN o0[64]
    DIRECTION OUTPUT ;
    USE SIGNAL ;
    PORT
      LAYER M5 ;
        RECT  15.504 0 15.528 0.192 ;
    END
  END o0[64]
  PIN o0[65]
    DIRECTION OUTPUT ;
    USE SIGNAL ;
    PORT
      LAYER M5 ;
        RECT  15.696 0 15.72 0.192 ;
    END
  END o0[65]
  PIN o0[66]
    DIRECTION OUTPUT ;
    USE SIGNAL ;
    PORT
      LAYER M5 ;
        RECT  15.84 0 15.864 0.192 ;
    END
  END o0[66]
  PIN o0[67]
    DIRECTION OUTPUT ;
    USE SIGNAL ;
    PORT
      LAYER M5 ;
        RECT  16.032 0 16.056 0.192 ;
    END
  END o0[67]
  PIN o0[68]
    DIRECTION OUTPUT ;
    USE SIGNAL ;
    PORT
      LAYER M5 ;
        RECT  16.368 0 16.392 0.192 ;
    END
  END o0[68]
  PIN o0[69]
    DIRECTION OUTPUT ;
    USE SIGNAL ;
    PORT
      LAYER M5 ;
        RECT  16.512 0 16.536 0.192 ;
    END
  END o0[69]
  PIN o0[6]
    DIRECTION OUTPUT ;
    USE SIGNAL ;
    PORT
      LAYER M5 ;
        RECT  5.52 0 5.544 0.192 ;
    END
  END o0[6]
  PIN o0[70]
    DIRECTION OUTPUT ;
    USE SIGNAL ;
    PORT
      LAYER M5 ;
        RECT  16.704 0 16.728 0.192 ;
    END
  END o0[70]
  PIN o0[71]
    DIRECTION OUTPUT ;
    USE SIGNAL ;
    PORT
      LAYER M5 ;
        RECT  16.896 0 16.92 0.192 ;
    END
  END o0[71]
  PIN o0[72]
    DIRECTION OUTPUT ;
    USE SIGNAL ;
    PORT
      LAYER M5 ;
        RECT  17.04 0 17.064 0.192 ;
    END
  END o0[72]
  PIN o0[73]
    DIRECTION OUTPUT ;
    USE SIGNAL ;
    PORT
      LAYER M5 ;
        RECT  17.232 0 17.256 0.192 ;
    END
  END o0[73]
  PIN o0[74]
    DIRECTION OUTPUT ;
    USE SIGNAL ;
    PORT
      LAYER M5 ;
        RECT  17.376 0 17.4 0.192 ;
    END
  END o0[74]
  PIN o0[75]
    DIRECTION OUTPUT ;
    USE SIGNAL ;
    PORT
      LAYER M5 ;
        RECT  17.568 0 17.592 0.192 ;
    END
  END o0[75]
  PIN o0[76]
    DIRECTION OUTPUT ;
    USE SIGNAL ;
    PORT
      LAYER M5 ;
        RECT  17.712 0 17.736 0.192 ;
    END
  END o0[76]
  PIN o0[77]
    DIRECTION OUTPUT ;
    USE SIGNAL ;
    PORT
      LAYER M5 ;
        RECT  17.904 0 17.928 0.192 ;
    END
  END o0[77]
  PIN o0[78]
    DIRECTION OUTPUT ;
    USE SIGNAL ;
    PORT
      LAYER M5 ;
        RECT  18.096 0 18.12 0.192 ;
    END
  END o0[78]
  PIN o0[79]
    DIRECTION OUTPUT ;
    USE SIGNAL ;
    PORT
      LAYER M5 ;
        RECT  18.24 0 18.264 0.192 ;
    END
  END o0[79]
  PIN o0[7]
    DIRECTION OUTPUT ;
    USE SIGNAL ;
    PORT
      LAYER M5 ;
        RECT  5.712 0 5.736 0.192 ;
    END
  END o0[7]
  PIN o0[80]
    DIRECTION OUTPUT ;
    USE SIGNAL ;
    PORT
      LAYER M5 ;
        RECT  18.432 0 18.456 0.192 ;
    END
  END o0[80]
  PIN o0[81]
    DIRECTION OUTPUT ;
    USE SIGNAL ;
    PORT
      LAYER M5 ;
        RECT  18.576 0 18.6 0.192 ;
    END
  END o0[81]
  PIN o0[82]
    DIRECTION OUTPUT ;
    USE SIGNAL ;
    PORT
      LAYER M5 ;
        RECT  18.768 0 18.792 0.192 ;
    END
  END o0[82]
  PIN o0[83]
    DIRECTION OUTPUT ;
    USE SIGNAL ;
    PORT
      LAYER M5 ;
        RECT  18.96 0 18.984 0.192 ;
    END
  END o0[83]
  PIN o0[84]
    DIRECTION OUTPUT ;
    USE SIGNAL ;
    PORT
      LAYER M5 ;
        RECT  19.104 0 19.128 0.192 ;
    END
  END o0[84]
  PIN o0[85]
    DIRECTION OUTPUT ;
    USE SIGNAL ;
    PORT
      LAYER M5 ;
        RECT  19.296 0 19.32 0.192 ;
    END
  END o0[85]
  PIN o0[86]
    DIRECTION OUTPUT ;
    USE SIGNAL ;
    PORT
      LAYER M5 ;
        RECT  19.44 0 19.464 0.192 ;
    END
  END o0[86]
  PIN o0[87]
    DIRECTION OUTPUT ;
    USE SIGNAL ;
    PORT
      LAYER M5 ;
        RECT  19.632 0 19.656 0.192 ;
    END
  END o0[87]
  PIN o0[88]
    DIRECTION OUTPUT ;
    USE SIGNAL ;
    PORT
      LAYER M5 ;
        RECT  19.776 0 19.8 0.192 ;
    END
  END o0[88]
  PIN o0[89]
    DIRECTION OUTPUT ;
    USE SIGNAL ;
    PORT
      LAYER M5 ;
        RECT  19.968 0 19.992 0.192 ;
    END
  END o0[89]
  PIN o0[8]
    DIRECTION OUTPUT ;
    USE SIGNAL ;
    PORT
      LAYER M5 ;
        RECT  5.904 0 5.928 0.192 ;
    END
  END o0[8]
  PIN o0[90]
    DIRECTION OUTPUT ;
    USE SIGNAL ;
    PORT
      LAYER M5 ;
        RECT  20.16 0 20.184 0.192 ;
    END
  END o0[90]
  PIN o0[91]
    DIRECTION OUTPUT ;
    USE SIGNAL ;
    PORT
      LAYER M5 ;
        RECT  20.304 0 20.328 0.192 ;
    END
  END o0[91]
  PIN o0[92]
    DIRECTION OUTPUT ;
    USE SIGNAL ;
    PORT
      LAYER M5 ;
        RECT  20.496 0 20.52 0.192 ;
    END
  END o0[92]
  PIN o0[93]
    DIRECTION OUTPUT ;
    USE SIGNAL ;
    PORT
      LAYER M5 ;
        RECT  20.64 0 20.664 0.192 ;
    END
  END o0[93]
  PIN o0[94]
    DIRECTION OUTPUT ;
    USE SIGNAL ;
    PORT
      LAYER M5 ;
        RECT  20.832 0 20.856 0.192 ;
    END
  END o0[94]
  PIN o0[95]
    DIRECTION OUTPUT ;
    USE SIGNAL ;
    PORT
      LAYER M5 ;
        RECT  20.976 0 21 0.192 ;
    END
  END o0[95]
  PIN o0[96]
    DIRECTION OUTPUT ;
    USE SIGNAL ;
    PORT
      LAYER M5 ;
        RECT  21.168 0 21.192 0.192 ;
    END
  END o0[96]
  PIN o0[97]
    DIRECTION OUTPUT ;
    USE SIGNAL ;
    PORT
      LAYER M5 ;
        RECT  21.36 0 21.384 0.192 ;
    END
  END o0[97]
  PIN o0[98]
    DIRECTION OUTPUT ;
    USE SIGNAL ;
    PORT
      LAYER M5 ;
        RECT  21.504 0 21.528 0.192 ;
    END
  END o0[98]
  PIN o0[99]
    DIRECTION OUTPUT ;
    USE SIGNAL ;
    PORT
      LAYER M5 ;
        RECT  21.696 0 21.72 0.192 ;
    END
  END o0[99]
  PIN o0[9]
    DIRECTION OUTPUT ;
    USE SIGNAL ;
    PORT
      LAYER M5 ;
        RECT  6.048 0 6.072 0.192 ;
    END
  END o0[9]
  PIN o1[0]
    DIRECTION OUTPUT ;
    USE SIGNAL ;
    PORT
      LAYER M5 ;
        RECT  28.272 0 28.296 0.192 ;
    END
  END o1[0]
  PIN o1[100]
    DIRECTION OUTPUT ;
    USE SIGNAL ;
    PORT
      LAYER M5 ;
        RECT  45.6 0 45.624 0.192 ;
    END
  END o1[100]
  PIN o1[101]
    DIRECTION OUTPUT ;
    USE SIGNAL ;
    PORT
      LAYER M5 ;
        RECT  45.792 0 45.816 0.192 ;
    END
  END o1[101]
  PIN o1[102]
    DIRECTION OUTPUT ;
    USE SIGNAL ;
    PORT
      LAYER M5 ;
        RECT  45.936 0 45.96 0.192 ;
    END
  END o1[102]
  PIN o1[103]
    DIRECTION OUTPUT ;
    USE SIGNAL ;
    PORT
      LAYER M5 ;
        RECT  46.128 0 46.152 0.192 ;
    END
  END o1[103]
  PIN o1[104]
    DIRECTION OUTPUT ;
    USE SIGNAL ;
    PORT
      LAYER M5 ;
        RECT  46.32 0 46.344 0.192 ;
    END
  END o1[104]
  PIN o1[105]
    DIRECTION OUTPUT ;
    USE SIGNAL ;
    PORT
      LAYER M5 ;
        RECT  46.464 0 46.488 0.192 ;
    END
  END o1[105]
  PIN o1[106]
    DIRECTION OUTPUT ;
    USE SIGNAL ;
    PORT
      LAYER M5 ;
        RECT  46.656 0 46.68 0.192 ;
    END
  END o1[106]
  PIN o1[107]
    DIRECTION OUTPUT ;
    USE SIGNAL ;
    PORT
      LAYER M5 ;
        RECT  46.8 0 46.824 0.192 ;
    END
  END o1[107]
  PIN o1[108]
    DIRECTION OUTPUT ;
    USE SIGNAL ;
    PORT
      LAYER M5 ;
        RECT  46.992 0 47.016 0.192 ;
    END
  END o1[108]
  PIN o1[109]
    DIRECTION OUTPUT ;
    USE SIGNAL ;
    PORT
      LAYER M5 ;
        RECT  47.184 0 47.208 0.192 ;
    END
  END o1[109]
  PIN o1[10]
    DIRECTION OUTPUT ;
    USE SIGNAL ;
    PORT
      LAYER M5 ;
        RECT  30 0 30.024 0.192 ;
    END
  END o1[10]
  PIN o1[110]
    DIRECTION OUTPUT ;
    USE SIGNAL ;
    PORT
      LAYER M5 ;
        RECT  47.328 0 47.352 0.192 ;
    END
  END o1[110]
  PIN o1[111]
    DIRECTION OUTPUT ;
    USE SIGNAL ;
    PORT
      LAYER M5 ;
        RECT  47.52 0 47.544 0.192 ;
    END
  END o1[111]
  PIN o1[112]
    DIRECTION OUTPUT ;
    USE SIGNAL ;
    PORT
      LAYER M5 ;
        RECT  47.664 0 47.688 0.192 ;
    END
  END o1[112]
  PIN o1[113]
    DIRECTION OUTPUT ;
    USE SIGNAL ;
    PORT
      LAYER M5 ;
        RECT  47.856 0 47.88 0.192 ;
    END
  END o1[113]
  PIN o1[114]
    DIRECTION OUTPUT ;
    USE SIGNAL ;
    PORT
      LAYER M5 ;
        RECT  48 0 48.024 0.192 ;
    END
  END o1[114]
  PIN o1[115]
    DIRECTION OUTPUT ;
    USE SIGNAL ;
    PORT
      LAYER M5 ;
        RECT  48.192 0 48.216 0.192 ;
    END
  END o1[115]
  PIN o1[116]
    DIRECTION OUTPUT ;
    USE SIGNAL ;
    PORT
      LAYER M5 ;
        RECT  48.384 0 48.408 0.192 ;
    END
  END o1[116]
  PIN o1[117]
    DIRECTION OUTPUT ;
    USE SIGNAL ;
    PORT
      LAYER M5 ;
        RECT  48.528 0 48.552 0.192 ;
    END
  END o1[117]
  PIN o1[118]
    DIRECTION OUTPUT ;
    USE SIGNAL ;
    PORT
      LAYER M5 ;
        RECT  48.72 0 48.744 0.192 ;
    END
  END o1[118]
  PIN o1[119]
    DIRECTION OUTPUT ;
    USE SIGNAL ;
    PORT
      LAYER M5 ;
        RECT  48.864 0 48.888 0.192 ;
    END
  END o1[119]
  PIN o1[11]
    DIRECTION OUTPUT ;
    USE SIGNAL ;
    PORT
      LAYER M5 ;
        RECT  30.144 0 30.168 0.192 ;
    END
  END o1[11]
  PIN o1[120]
    DIRECTION OUTPUT ;
    USE SIGNAL ;
    PORT
      LAYER M5 ;
        RECT  49.056 0 49.08 0.192 ;
    END
  END o1[120]
  PIN o1[121]
    DIRECTION OUTPUT ;
    USE SIGNAL ;
    PORT
      LAYER M5 ;
        RECT  49.2 0 49.224 0.192 ;
    END
  END o1[121]
  PIN o1[122]
    DIRECTION OUTPUT ;
    USE SIGNAL ;
    PORT
      LAYER M5 ;
        RECT  49.392 0 49.416 0.192 ;
    END
  END o1[122]
  PIN o1[123]
    DIRECTION OUTPUT ;
    USE SIGNAL ;
    PORT
      LAYER M5 ;
        RECT  49.584 0 49.608 0.192 ;
    END
  END o1[123]
  PIN o1[124]
    DIRECTION OUTPUT ;
    USE SIGNAL ;
    PORT
      LAYER M5 ;
        RECT  49.728 0 49.752 0.192 ;
    END
  END o1[124]
  PIN o1[125]
    DIRECTION OUTPUT ;
    USE SIGNAL ;
    PORT
      LAYER M5 ;
        RECT  49.92 0 49.944 0.192 ;
    END
  END o1[125]
  PIN o1[126]
    DIRECTION OUTPUT ;
    USE SIGNAL ;
    PORT
      LAYER M5 ;
        RECT  50.064 0 50.088 0.192 ;
    END
  END o1[126]
  PIN o1[127]
    DIRECTION OUTPUT ;
    USE SIGNAL ;
    PORT
      LAYER M5 ;
        RECT  50.256 0 50.28 0.192 ;
    END
  END o1[127]
  PIN o1[128]
    DIRECTION OUTPUT ;
    USE SIGNAL ;
    PORT
      LAYER M5 ;
        RECT  50.448 0 50.472 0.192 ;
    END
  END o1[128]
  PIN o1[129]
    DIRECTION OUTPUT ;
    USE SIGNAL ;
    PORT
      LAYER M5 ;
        RECT  50.592 0 50.616 0.192 ;
    END
  END o1[129]
  PIN o1[12]
    DIRECTION OUTPUT ;
    USE SIGNAL ;
    PORT
      LAYER M5 ;
        RECT  30.336 0 30.36 0.192 ;
    END
  END o1[12]
  PIN o1[130]
    DIRECTION OUTPUT ;
    USE SIGNAL ;
    PORT
      LAYER M5 ;
        RECT  50.784 0 50.808 0.192 ;
    END
  END o1[130]
  PIN o1[131]
    DIRECTION OUTPUT ;
    USE SIGNAL ;
    PORT
      LAYER M5 ;
        RECT  50.928 0 50.952 0.192 ;
    END
  END o1[131]
  PIN o1[132]
    DIRECTION OUTPUT ;
    USE SIGNAL ;
    PORT
      LAYER M5 ;
        RECT  51.12 0 51.144 0.192 ;
    END
  END o1[132]
  PIN o1[133]
    DIRECTION OUTPUT ;
    USE SIGNAL ;
    PORT
      LAYER M5 ;
        RECT  51.264 0 51.288 0.192 ;
    END
  END o1[133]
  PIN o1[134]
    DIRECTION OUTPUT ;
    USE SIGNAL ;
    PORT
      LAYER M5 ;
        RECT  51.456 0 51.48 0.192 ;
    END
  END o1[134]
  PIN o1[135]
    DIRECTION OUTPUT ;
    USE SIGNAL ;
    PORT
      LAYER M5 ;
        RECT  51.648 0 51.672 0.192 ;
    END
  END o1[135]
  PIN o1[13]
    DIRECTION OUTPUT ;
    USE SIGNAL ;
    PORT
      LAYER M5 ;
        RECT  30.48 0 30.504 0.192 ;
    END
  END o1[13]
  PIN o1[14]
    DIRECTION OUTPUT ;
    USE SIGNAL ;
    PORT
      LAYER M5 ;
        RECT  30.672 0 30.696 0.192 ;
    END
  END o1[14]
  PIN o1[15]
    DIRECTION OUTPUT ;
    USE SIGNAL ;
    PORT
      LAYER M5 ;
        RECT  30.864 0 30.888 0.192 ;
    END
  END o1[15]
  PIN o1[16]
    DIRECTION OUTPUT ;
    USE SIGNAL ;
    PORT
      LAYER M5 ;
        RECT  31.008 0 31.032 0.192 ;
    END
  END o1[16]
  PIN o1[17]
    DIRECTION OUTPUT ;
    USE SIGNAL ;
    PORT
      LAYER M5 ;
        RECT  31.2 0 31.224 0.192 ;
    END
  END o1[17]
  PIN o1[18]
    DIRECTION OUTPUT ;
    USE SIGNAL ;
    PORT
      LAYER M5 ;
        RECT  31.344 0 31.368 0.192 ;
    END
  END o1[18]
  PIN o1[19]
    DIRECTION OUTPUT ;
    USE SIGNAL ;
    PORT
      LAYER M5 ;
        RECT  31.536 0 31.56 0.192 ;
    END
  END o1[19]
  PIN o1[1]
    DIRECTION OUTPUT ;
    USE SIGNAL ;
    PORT
      LAYER M5 ;
        RECT  28.416 0 28.44 0.192 ;
    END
  END o1[1]
  PIN o1[20]
    DIRECTION OUTPUT ;
    USE SIGNAL ;
    PORT
      LAYER M5 ;
        RECT  31.68 0 31.704 0.192 ;
    END
  END o1[20]
  PIN o1[21]
    DIRECTION OUTPUT ;
    USE SIGNAL ;
    PORT
      LAYER M5 ;
        RECT  31.872 0 31.896 0.192 ;
    END
  END o1[21]
  PIN o1[22]
    DIRECTION OUTPUT ;
    USE SIGNAL ;
    PORT
      LAYER M5 ;
        RECT  32.064 0 32.088 0.192 ;
    END
  END o1[22]
  PIN o1[23]
    DIRECTION OUTPUT ;
    USE SIGNAL ;
    PORT
      LAYER M5 ;
        RECT  32.208 0 32.232 0.192 ;
    END
  END o1[23]
  PIN o1[24]
    DIRECTION OUTPUT ;
    USE SIGNAL ;
    PORT
      LAYER M5 ;
        RECT  32.4 0 32.424 0.192 ;
    END
  END o1[24]
  PIN o1[25]
    DIRECTION OUTPUT ;
    USE SIGNAL ;
    PORT
      LAYER M5 ;
        RECT  32.544 0 32.568 0.192 ;
    END
  END o1[25]
  PIN o1[26]
    DIRECTION OUTPUT ;
    USE SIGNAL ;
    PORT
      LAYER M5 ;
        RECT  32.736 0 32.76 0.192 ;
    END
  END o1[26]
  PIN o1[27]
    DIRECTION OUTPUT ;
    USE SIGNAL ;
    PORT
      LAYER M5 ;
        RECT  32.928 0 32.952 0.192 ;
    END
  END o1[27]
  PIN o1[28]
    DIRECTION OUTPUT ;
    USE SIGNAL ;
    PORT
      LAYER M5 ;
        RECT  33.072 0 33.096 0.192 ;
    END
  END o1[28]
  PIN o1[29]
    DIRECTION OUTPUT ;
    USE SIGNAL ;
    PORT
      LAYER M5 ;
        RECT  33.264 0 33.288 0.192 ;
    END
  END o1[29]
  PIN o1[2]
    DIRECTION OUTPUT ;
    USE SIGNAL ;
    PORT
      LAYER M5 ;
        RECT  28.608 0 28.632 0.192 ;
    END
  END o1[2]
  PIN o1[30]
    DIRECTION OUTPUT ;
    USE SIGNAL ;
    PORT
      LAYER M5 ;
        RECT  33.408 0 33.432 0.192 ;
    END
  END o1[30]
  PIN o1[31]
    DIRECTION OUTPUT ;
    USE SIGNAL ;
    PORT
      LAYER M5 ;
        RECT  33.6 0 33.624 0.192 ;
    END
  END o1[31]
  PIN o1[32]
    DIRECTION OUTPUT ;
    USE SIGNAL ;
    PORT
      LAYER M5 ;
        RECT  33.744 0 33.768 0.192 ;
    END
  END o1[32]
  PIN o1[33]
    DIRECTION OUTPUT ;
    USE SIGNAL ;
    PORT
      LAYER M5 ;
        RECT  33.936 0 33.96 0.192 ;
    END
  END o1[33]
  PIN o1[34]
    DIRECTION OUTPUT ;
    USE SIGNAL ;
    PORT
      LAYER M5 ;
        RECT  34.128 0 34.152 0.192 ;
    END
  END o1[34]
  PIN o1[35]
    DIRECTION OUTPUT ;
    USE SIGNAL ;
    PORT
      LAYER M5 ;
        RECT  34.272 0 34.296 0.192 ;
    END
  END o1[35]
  PIN o1[36]
    DIRECTION OUTPUT ;
    USE SIGNAL ;
    PORT
      LAYER M5 ;
        RECT  34.464 0 34.488 0.192 ;
    END
  END o1[36]
  PIN o1[37]
    DIRECTION OUTPUT ;
    USE SIGNAL ;
    PORT
      LAYER M5 ;
        RECT  34.608 0 34.632 0.192 ;
    END
  END o1[37]
  PIN o1[38]
    DIRECTION OUTPUT ;
    USE SIGNAL ;
    PORT
      LAYER M5 ;
        RECT  34.8 0 34.824 0.192 ;
    END
  END o1[38]
  PIN o1[39]
    DIRECTION OUTPUT ;
    USE SIGNAL ;
    PORT
      LAYER M5 ;
        RECT  34.944 0 34.968 0.192 ;
    END
  END o1[39]
  PIN o1[3]
    DIRECTION OUTPUT ;
    USE SIGNAL ;
    PORT
      LAYER M5 ;
        RECT  28.8 0 28.824 0.192 ;
    END
  END o1[3]
  PIN o1[40]
    DIRECTION OUTPUT ;
    USE SIGNAL ;
    PORT
      LAYER M5 ;
        RECT  35.136 0 35.16 0.192 ;
    END
  END o1[40]
  PIN o1[41]
    DIRECTION OUTPUT ;
    USE SIGNAL ;
    PORT
      LAYER M5 ;
        RECT  35.328 0 35.352 0.192 ;
    END
  END o1[41]
  PIN o1[42]
    DIRECTION OUTPUT ;
    USE SIGNAL ;
    PORT
      LAYER M5 ;
        RECT  35.472 0 35.496 0.192 ;
    END
  END o1[42]
  PIN o1[43]
    DIRECTION OUTPUT ;
    USE SIGNAL ;
    PORT
      LAYER M5 ;
        RECT  35.664 0 35.688 0.192 ;
    END
  END o1[43]
  PIN o1[44]
    DIRECTION OUTPUT ;
    USE SIGNAL ;
    PORT
      LAYER M5 ;
        RECT  35.808 0 35.832 0.192 ;
    END
  END o1[44]
  PIN o1[45]
    DIRECTION OUTPUT ;
    USE SIGNAL ;
    PORT
      LAYER M5 ;
        RECT  36 0 36.024 0.192 ;
    END
  END o1[45]
  PIN o1[46]
    DIRECTION OUTPUT ;
    USE SIGNAL ;
    PORT
      LAYER M5 ;
        RECT  36.192 0 36.216 0.192 ;
    END
  END o1[46]
  PIN o1[47]
    DIRECTION OUTPUT ;
    USE SIGNAL ;
    PORT
      LAYER M5 ;
        RECT  36.336 0 36.36 0.192 ;
    END
  END o1[47]
  PIN o1[48]
    DIRECTION OUTPUT ;
    USE SIGNAL ;
    PORT
      LAYER M5 ;
        RECT  36.528 0 36.552 0.192 ;
    END
  END o1[48]
  PIN o1[49]
    DIRECTION OUTPUT ;
    USE SIGNAL ;
    PORT
      LAYER M5 ;
        RECT  36.672 0 36.696 0.192 ;
    END
  END o1[49]
  PIN o1[4]
    DIRECTION OUTPUT ;
    USE SIGNAL ;
    PORT
      LAYER M5 ;
        RECT  28.944 0 28.968 0.192 ;
    END
  END o1[4]
  PIN o1[50]
    DIRECTION OUTPUT ;
    USE SIGNAL ;
    PORT
      LAYER M5 ;
        RECT  36.864 0 36.888 0.192 ;
    END
  END o1[50]
  PIN o1[51]
    DIRECTION OUTPUT ;
    USE SIGNAL ;
    PORT
      LAYER M5 ;
        RECT  37.008 0 37.032 0.192 ;
    END
  END o1[51]
  PIN o1[52]
    DIRECTION OUTPUT ;
    USE SIGNAL ;
    PORT
      LAYER M5 ;
        RECT  37.2 0 37.224 0.192 ;
    END
  END o1[52]
  PIN o1[53]
    DIRECTION OUTPUT ;
    USE SIGNAL ;
    PORT
      LAYER M5 ;
        RECT  37.392 0 37.416 0.192 ;
    END
  END o1[53]
  PIN o1[54]
    DIRECTION OUTPUT ;
    USE SIGNAL ;
    PORT
      LAYER M5 ;
        RECT  37.536 0 37.56 0.192 ;
    END
  END o1[54]
  PIN o1[55]
    DIRECTION OUTPUT ;
    USE SIGNAL ;
    PORT
      LAYER M5 ;
        RECT  37.728 0 37.752 0.192 ;
    END
  END o1[55]
  PIN o1[56]
    DIRECTION OUTPUT ;
    USE SIGNAL ;
    PORT
      LAYER M5 ;
        RECT  37.872 0 37.896 0.192 ;
    END
  END o1[56]
  PIN o1[57]
    DIRECTION OUTPUT ;
    USE SIGNAL ;
    PORT
      LAYER M5 ;
        RECT  38.064 0 38.088 0.192 ;
    END
  END o1[57]
  PIN o1[58]
    DIRECTION OUTPUT ;
    USE SIGNAL ;
    PORT
      LAYER M5 ;
        RECT  38.208 0 38.232 0.192 ;
    END
  END o1[58]
  PIN o1[59]
    DIRECTION OUTPUT ;
    USE SIGNAL ;
    PORT
      LAYER M5 ;
        RECT  38.4 0 38.424 0.192 ;
    END
  END o1[59]
  PIN o1[5]
    DIRECTION OUTPUT ;
    USE SIGNAL ;
    PORT
      LAYER M5 ;
        RECT  29.136 0 29.16 0.192 ;
    END
  END o1[5]
  PIN o1[60]
    DIRECTION OUTPUT ;
    USE SIGNAL ;
    PORT
      LAYER M5 ;
        RECT  38.592 0 38.616 0.192 ;
    END
  END o1[60]
  PIN o1[61]
    DIRECTION OUTPUT ;
    USE SIGNAL ;
    PORT
      LAYER M5 ;
        RECT  38.736 0 38.76 0.192 ;
    END
  END o1[61]
  PIN o1[62]
    DIRECTION OUTPUT ;
    USE SIGNAL ;
    PORT
      LAYER M5 ;
        RECT  38.928 0 38.952 0.192 ;
    END
  END o1[62]
  PIN o1[63]
    DIRECTION OUTPUT ;
    USE SIGNAL ;
    PORT
      LAYER M5 ;
        RECT  39.072 0 39.096 0.192 ;
    END
  END o1[63]
  PIN o1[64]
    DIRECTION OUTPUT ;
    USE SIGNAL ;
    PORT
      LAYER M5 ;
        RECT  39.264 0 39.288 0.192 ;
    END
  END o1[64]
  PIN o1[65]
    DIRECTION OUTPUT ;
    USE SIGNAL ;
    PORT
      LAYER M5 ;
        RECT  39.456 0 39.48 0.192 ;
    END
  END o1[65]
  PIN o1[66]
    DIRECTION OUTPUT ;
    USE SIGNAL ;
    PORT
      LAYER M5 ;
        RECT  39.6 0 39.624 0.192 ;
    END
  END o1[66]
  PIN o1[67]
    DIRECTION OUTPUT ;
    USE SIGNAL ;
    PORT
      LAYER M5 ;
        RECT  39.792 0 39.816 0.192 ;
    END
  END o1[67]
  PIN o1[68]
    DIRECTION OUTPUT ;
    USE SIGNAL ;
    PORT
      LAYER M5 ;
        RECT  40.128 0 40.152 0.192 ;
    END
  END o1[68]
  PIN o1[69]
    DIRECTION OUTPUT ;
    USE SIGNAL ;
    PORT
      LAYER M5 ;
        RECT  40.272 0 40.296 0.192 ;
    END
  END o1[69]
  PIN o1[6]
    DIRECTION OUTPUT ;
    USE SIGNAL ;
    PORT
      LAYER M5 ;
        RECT  29.28 0 29.304 0.192 ;
    END
  END o1[6]
  PIN o1[70]
    DIRECTION OUTPUT ;
    USE SIGNAL ;
    PORT
      LAYER M5 ;
        RECT  40.464 0 40.488 0.192 ;
    END
  END o1[70]
  PIN o1[71]
    DIRECTION OUTPUT ;
    USE SIGNAL ;
    PORT
      LAYER M5 ;
        RECT  40.656 0 40.68 0.192 ;
    END
  END o1[71]
  PIN o1[72]
    DIRECTION OUTPUT ;
    USE SIGNAL ;
    PORT
      LAYER M5 ;
        RECT  40.8 0 40.824 0.192 ;
    END
  END o1[72]
  PIN o1[73]
    DIRECTION OUTPUT ;
    USE SIGNAL ;
    PORT
      LAYER M5 ;
        RECT  40.992 0 41.016 0.192 ;
    END
  END o1[73]
  PIN o1[74]
    DIRECTION OUTPUT ;
    USE SIGNAL ;
    PORT
      LAYER M5 ;
        RECT  41.136 0 41.16 0.192 ;
    END
  END o1[74]
  PIN o1[75]
    DIRECTION OUTPUT ;
    USE SIGNAL ;
    PORT
      LAYER M5 ;
        RECT  41.328 0 41.352 0.192 ;
    END
  END o1[75]
  PIN o1[76]
    DIRECTION OUTPUT ;
    USE SIGNAL ;
    PORT
      LAYER M5 ;
        RECT  41.472 0 41.496 0.192 ;
    END
  END o1[76]
  PIN o1[77]
    DIRECTION OUTPUT ;
    USE SIGNAL ;
    PORT
      LAYER M5 ;
        RECT  41.664 0 41.688 0.192 ;
    END
  END o1[77]
  PIN o1[78]
    DIRECTION OUTPUT ;
    USE SIGNAL ;
    PORT
      LAYER M5 ;
        RECT  41.856 0 41.88 0.192 ;
    END
  END o1[78]
  PIN o1[79]
    DIRECTION OUTPUT ;
    USE SIGNAL ;
    PORT
      LAYER M5 ;
        RECT  42 0 42.024 0.192 ;
    END
  END o1[79]
  PIN o1[7]
    DIRECTION OUTPUT ;
    USE SIGNAL ;
    PORT
      LAYER M5 ;
        RECT  29.472 0 29.496 0.192 ;
    END
  END o1[7]
  PIN o1[80]
    DIRECTION OUTPUT ;
    USE SIGNAL ;
    PORT
      LAYER M5 ;
        RECT  42.192 0 42.216 0.192 ;
    END
  END o1[80]
  PIN o1[81]
    DIRECTION OUTPUT ;
    USE SIGNAL ;
    PORT
      LAYER M5 ;
        RECT  42.336 0 42.36 0.192 ;
    END
  END o1[81]
  PIN o1[82]
    DIRECTION OUTPUT ;
    USE SIGNAL ;
    PORT
      LAYER M5 ;
        RECT  42.528 0 42.552 0.192 ;
    END
  END o1[82]
  PIN o1[83]
    DIRECTION OUTPUT ;
    USE SIGNAL ;
    PORT
      LAYER M5 ;
        RECT  42.72 0 42.744 0.192 ;
    END
  END o1[83]
  PIN o1[84]
    DIRECTION OUTPUT ;
    USE SIGNAL ;
    PORT
      LAYER M5 ;
        RECT  42.864 0 42.888 0.192 ;
    END
  END o1[84]
  PIN o1[85]
    DIRECTION OUTPUT ;
    USE SIGNAL ;
    PORT
      LAYER M5 ;
        RECT  43.056 0 43.08 0.192 ;
    END
  END o1[85]
  PIN o1[86]
    DIRECTION OUTPUT ;
    USE SIGNAL ;
    PORT
      LAYER M5 ;
        RECT  43.2 0 43.224 0.192 ;
    END
  END o1[86]
  PIN o1[87]
    DIRECTION OUTPUT ;
    USE SIGNAL ;
    PORT
      LAYER M5 ;
        RECT  43.392 0 43.416 0.192 ;
    END
  END o1[87]
  PIN o1[88]
    DIRECTION OUTPUT ;
    USE SIGNAL ;
    PORT
      LAYER M5 ;
        RECT  43.536 0 43.56 0.192 ;
    END
  END o1[88]
  PIN o1[89]
    DIRECTION OUTPUT ;
    USE SIGNAL ;
    PORT
      LAYER M5 ;
        RECT  43.728 0 43.752 0.192 ;
    END
  END o1[89]
  PIN o1[8]
    DIRECTION OUTPUT ;
    USE SIGNAL ;
    PORT
      LAYER M5 ;
        RECT  29.664 0 29.688 0.192 ;
    END
  END o1[8]
  PIN o1[90]
    DIRECTION OUTPUT ;
    USE SIGNAL ;
    PORT
      LAYER M5 ;
        RECT  43.92 0 43.944 0.192 ;
    END
  END o1[90]
  PIN o1[91]
    DIRECTION OUTPUT ;
    USE SIGNAL ;
    PORT
      LAYER M5 ;
        RECT  44.064 0 44.088 0.192 ;
    END
  END o1[91]
  PIN o1[92]
    DIRECTION OUTPUT ;
    USE SIGNAL ;
    PORT
      LAYER M5 ;
        RECT  44.256 0 44.28 0.192 ;
    END
  END o1[92]
  PIN o1[93]
    DIRECTION OUTPUT ;
    USE SIGNAL ;
    PORT
      LAYER M5 ;
        RECT  44.4 0 44.424 0.192 ;
    END
  END o1[93]
  PIN o1[94]
    DIRECTION OUTPUT ;
    USE SIGNAL ;
    PORT
      LAYER M5 ;
        RECT  44.592 0 44.616 0.192 ;
    END
  END o1[94]
  PIN o1[95]
    DIRECTION OUTPUT ;
    USE SIGNAL ;
    PORT
      LAYER M5 ;
        RECT  44.736 0 44.76 0.192 ;
    END
  END o1[95]
  PIN o1[96]
    DIRECTION OUTPUT ;
    USE SIGNAL ;
    PORT
      LAYER M5 ;
        RECT  44.928 0 44.952 0.192 ;
    END
  END o1[96]
  PIN o1[97]
    DIRECTION OUTPUT ;
    USE SIGNAL ;
    PORT
      LAYER M5 ;
        RECT  45.12 0 45.144 0.192 ;
    END
  END o1[97]
  PIN o1[98]
    DIRECTION OUTPUT ;
    USE SIGNAL ;
    PORT
      LAYER M5 ;
        RECT  45.264 0 45.288 0.192 ;
    END
  END o1[98]
  PIN o1[99]
    DIRECTION OUTPUT ;
    USE SIGNAL ;
    PORT
      LAYER M5 ;
        RECT  45.456 0 45.48 0.192 ;
    END
  END o1[99]
  PIN o1[9]
    DIRECTION OUTPUT ;
    USE SIGNAL ;
    PORT
      LAYER M5 ;
        RECT  29.808 0 29.832 0.192 ;
    END
  END o1[9]
  PIN rs
    DIRECTION INPUT ;
    USE SIGNAL ;
    PORT
      LAYER M4 ;
        RECT  0 10.8 0.192 10.824 ;
    END
  END rs
  PIN VDD
    DIRECTION INOUT ;
    USE POWER ;
    PORT
      LAYER M5 ;
        RECT  53.892 2.151 54.012 19.449 ;
        RECT  51.192 2.151 51.312 19.449 ;
        RECT  48.492 2.151 48.612 19.449 ;
        RECT  45.792 2.151 45.912 19.449 ;
        RECT  43.092 2.151 43.212 19.449 ;
        RECT  40.392 2.151 40.512 19.449 ;
        RECT  37.692 2.151 37.812 19.449 ;
        RECT  34.992 2.151 35.112 19.449 ;
        RECT  32.292 2.151 32.412 19.449 ;
        RECT  29.592 2.151 29.712 19.449 ;
        RECT  26.892 2.151 27.012 19.449 ;
        RECT  24.192 2.151 24.312 19.449 ;
        RECT  21.492 2.151 21.612 19.449 ;
        RECT  18.792 2.151 18.912 19.449 ;
        RECT  16.092 2.151 16.212 19.449 ;
        RECT  13.392 2.151 13.512 19.449 ;
        RECT  10.692 2.151 10.812 19.449 ;
        RECT  7.992 2.151 8.112 19.449 ;
        RECT  5.292 2.151 5.412 19.449 ;
        RECT  2.592 2.151 2.712 19.449 ;
    END
  END VDD
  PIN VSS
    DIRECTION INOUT ;
    USE GROUND ;
    PORT
      LAYER M5 ;
        RECT  53.7 2.137 53.82 19.463 ;
        RECT  51 2.137 51.12 19.463 ;
        RECT  48.3 2.137 48.42 19.463 ;
        RECT  45.6 2.137 45.72 19.463 ;
        RECT  42.9 2.137 43.02 19.463 ;
        RECT  40.2 2.137 40.32 19.463 ;
        RECT  37.5 2.137 37.62 19.463 ;
        RECT  34.8 2.137 34.92 19.463 ;
        RECT  32.1 2.137 32.22 19.463 ;
        RECT  29.4 2.137 29.52 19.463 ;
        RECT  26.7 2.137 26.82 19.463 ;
        RECT  24 2.137 24.12 19.463 ;
        RECT  21.3 2.137 21.42 19.463 ;
        RECT  18.6 2.137 18.72 19.463 ;
        RECT  15.9 2.137 16.02 19.463 ;
        RECT  13.2 2.137 13.32 19.463 ;
        RECT  10.5 2.137 10.62 19.463 ;
        RECT  7.8 2.137 7.92 19.463 ;
        RECT  5.1 2.137 5.22 19.463 ;
        RECT  2.4 2.137 2.52 19.463 ;
    END
  END VSS
  OBS
    LAYER RVTN ;
     RECT  2.16 2.16 54 2.295 ;
     RECT  2.16 2.565 54 2.835 ;
     RECT  2.16 3.105 54 3.375 ;
     RECT  2.16 3.645 54 3.915 ;
     RECT  2.16 4.185 54 4.455 ;
     RECT  2.16 4.725 54 4.995 ;
     RECT  2.16 5.265 54 5.535 ;
     RECT  2.16 5.805 54 6.075 ;
     RECT  2.16 6.345 54 6.615 ;
     RECT  2.16 6.885 54 7.155 ;
     RECT  2.16 7.425 54 7.695 ;
     RECT  2.16 7.965 54 8.235 ;
     RECT  2.16 8.505 54 8.775 ;
     RECT  2.16 9.045 54 9.315 ;
     RECT  2.16 9.585 54 9.855 ;
     RECT  2.16 10.125 54 10.395 ;
     RECT  2.16 10.665 54 10.935 ;
     RECT  2.16 11.205 54 11.475 ;
     RECT  2.16 11.745 54 12.015 ;
     RECT  2.16 12.285 54 12.555 ;
     RECT  2.16 12.825 54 13.095 ;
     RECT  2.16 13.365 54 13.635 ;
     RECT  2.16 13.905 54 14.175 ;
     RECT  2.16 14.445 54 14.715 ;
     RECT  2.16 14.985 54 15.255 ;
     RECT  2.16 15.525 54 15.795 ;
     RECT  2.16 16.065 54 16.335 ;
     RECT  2.16 16.605 54 16.875 ;
     RECT  2.16 17.145 54 17.415 ;
     RECT  2.16 17.685 54 17.955 ;
     RECT  2.16 18.225 54 18.495 ;
     RECT  2.16 18.765 54 19.035 ;
     RECT  2.16 19.305 54 19.44 ;
    LAYER RVTP ;
     RECT  2.16 2.295 54 2.565 ;
     RECT  2.16 2.835 54 3.105 ;
     RECT  2.16 3.375 54 3.645 ;
     RECT  2.16 3.915 54 4.185 ;
     RECT  2.16 4.455 54 4.725 ;
     RECT  2.16 4.995 54 5.265 ;
     RECT  2.16 5.535 54 5.805 ;
     RECT  2.16 6.075 54 6.345 ;
     RECT  2.16 6.615 54 6.885 ;
     RECT  2.16 7.155 54 7.425 ;
     RECT  2.16 7.695 54 7.965 ;
     RECT  2.16 8.235 54 8.505 ;
     RECT  2.16 8.775 54 9.045 ;
     RECT  2.16 9.315 54 9.585 ;
     RECT  2.16 9.855 54 10.125 ;
     RECT  2.16 10.395 54 10.665 ;
     RECT  2.16 10.935 54 11.205 ;
     RECT  2.16 11.475 54 11.745 ;
     RECT  2.16 12.015 54 12.285 ;
     RECT  2.16 12.555 54 12.825 ;
     RECT  2.16 13.095 54 13.365 ;
     RECT  2.16 13.635 54 13.905 ;
     RECT  2.16 14.175 54 14.445 ;
     RECT  2.16 14.715 54 14.985 ;
     RECT  2.16 15.255 54 15.525 ;
     RECT  2.16 15.795 54 16.065 ;
     RECT  2.16 16.335 54 16.605 ;
     RECT  2.16 16.875 54 17.145 ;
     RECT  2.16 17.415 54 17.685 ;
     RECT  2.16 17.955 54 18.225 ;
     RECT  2.16 18.495 54 18.765 ;
     RECT  2.16 19.035 54 19.305 ;
    LAYER M1 ;
     RECT  2.16 2.151 54 19.449 ;
    LAYER M2 ;
     RECT  2.16 2.151 4.927 19.449 ;
     RECT  4.927 1.998 6.835 19.449 ;
     RECT  6.835 1.926 16.943 19.449 ;
     RECT  16.943 1.998 17.923 19.449 ;
     RECT  20.551 0.036 21.883 0.054 ;
     RECT  17.923 1.422 22.207 19.449 ;
     RECT  22.207 0.99 23.071 19.449 ;
     RECT  23.071 0.882 25.123 19.449 ;
     RECT  21.883 0.036 25.303 0.09 ;
     RECT  25.123 0.846 25.303 19.449 ;
     RECT  25.303 0.036 33.719 19.449 ;
     RECT  33.719 0.072 34.871 19.449 ;
     RECT  34.871 0.108 35.375 19.449 ;
     RECT  35.375 0.846 45.059 19.449 ;
     RECT  45.059 0.846 45.959 0.864 ;
     RECT  45.059 1.962 48.623 19.449 ;
     RECT  48.623 2.106 52.619 19.449 ;
     RECT  52.619 2.151 54 19.449 ;
     RECT  54 2.421 54.012 19.179 ;
    LAYER M3 ;
     RECT  20.556 0.031 20.574 0.043 ;
     RECT  20.232 0.043 20.574 0.091 ;
     RECT  21.888 0.067 21.906 0.091 ;
     RECT  33.696 0.031 33.714 0.091 ;
     RECT  34.848 0.067 34.866 0.091 ;
     RECT  33.696 0.091 34.866 0.103 ;
     RECT  21.888 0.091 22.158 0.139 ;
     RECT  19.944 0.091 20.574 0.187 ;
     RECT  21.816 0.139 22.158 0.187 ;
     RECT  25.308 0.103 25.326 0.187 ;
     RECT  33.696 0.103 35.37 0.221 ;
     RECT  21.816 0.187 25.794 0.235 ;
     RECT  48.78 0.187 48.798 0.235 ;
     RECT  30.78 0.235 30.798 0.283 ;
     RECT  31.86 0.187 31.878 0.317 ;
     RECT  30.096 0.283 30.87 0.365 ;
     RECT  30.852 0.365 30.87 0.413 ;
     RECT  32.94 0.187 32.958 0.523 ;
     RECT  36.108 0.475 36.126 0.523 ;
     RECT  44.352 0.475 44.37 0.523 ;
     RECT  4.788 0.187 4.806 0.571 ;
     RECT  5.688 0.187 5.706 0.571 ;
     RECT  6.948 0.187 6.966 0.571 ;
     RECT  8.136 0.187 8.154 0.571 ;
     RECT  45.468 0.475 45.486 0.571 ;
     RECT  48.78 0.235 48.87 0.571 ;
     RECT  19.656 0.187 20.574 0.811 ;
     RECT  42.192 0.571 42.21 0.811 ;
     RECT  43.236 0.187 43.254 0.811 ;
     RECT  45.108 0.571 45.486 0.841 ;
     RECT  46.26 0.571 46.278 0.841 ;
     RECT  11.916 0.571 11.934 0.859 ;
     RECT  42.192 0.811 43.254 0.877 ;
     RECT  44.028 0.523 44.37 0.877 ;
     RECT  38.124 0.571 38.754 0.907 ;
     RECT  39.6 0.571 39.618 0.907 ;
     RECT  40.5 0.187 40.518 0.955 ;
     RECT  32.94 0.523 33.174 1.003 ;
     RECT  42.192 0.877 44.37 1.021 ;
     RECT  45.108 0.841 46.278 1.021 ;
     RECT  4.788 0.571 5.706 1.099 ;
     RECT  28.476 0.571 28.494 1.099 ;
     RECT  38.124 0.907 39.618 1.099 ;
     RECT  40.464 0.955 40.518 1.099 ;
     RECT  42.192 1.021 46.278 1.099 ;
     RECT  4.5 1.099 5.706 1.147 ;
     RECT  6.516 0.571 6.966 1.147 ;
     RECT  8.136 0.571 8.334 1.147 ;
     RECT  30.096 0.365 30.114 1.147 ;
     RECT  38.124 1.099 40.518 1.147 ;
     RECT  48.744 0.571 48.87 1.147 ;
     RECT  49.608 0.571 49.626 1.147 ;
     RECT  50.94 0.571 50.958 1.147 ;
     RECT  29.88 1.147 30.114 1.339 ;
     RECT  38.124 1.147 40.59 1.435 ;
     RECT  41.364 1.099 46.278 1.435 ;
     RECT  15.84 0.235 15.858 1.579 ;
     RECT  34.308 0.221 35.262 1.627 ;
     RECT  36.108 0.523 36.666 1.627 ;
     RECT  38.124 1.435 46.278 1.627 ;
     RECT  47.772 0.523 47.79 1.627 ;
     RECT  48.744 1.147 50.958 1.627 ;
     RECT  34.308 1.627 36.666 1.675 ;
     RECT  37.44 1.627 46.278 1.675 ;
     RECT  4.5 1.147 8.334 1.723 ;
     RECT  9.288 1.147 9.882 1.723 ;
     RECT  11.088 0.571 11.106 1.723 ;
     RECT  11.916 0.859 12.078 1.723 ;
     RECT  15.372 1.579 15.858 1.723 ;
     RECT  21.816 0.235 26.514 1.723 ;
     RECT  34.308 1.675 46.278 1.723 ;
     RECT  47.016 0.187 47.034 1.723 ;
     RECT  47.772 1.627 50.958 1.723 ;
     RECT  29.808 1.339 30.114 1.759 ;
     RECT  31.176 0.523 31.338 1.759 ;
     RECT  32.292 1.003 33.174 1.759 ;
     RECT  4.5 1.723 11.106 1.771 ;
     RECT  11.916 1.723 15.894 1.771 ;
     RECT  16.74 1.723 17.082 1.771 ;
     RECT  28.476 1.099 28.998 1.771 ;
     RECT  29.808 1.759 31.338 1.771 ;
     RECT  28.476 1.771 31.338 1.867 ;
     RECT  19.044 0.811 20.574 1.876 ;
     RECT  21.816 1.723 27.198 1.876 ;
     RECT  28.404 1.867 31.338 1.876 ;
     RECT  21.816 1.876 31.338 1.915 ;
     RECT  19.044 1.876 20.754 1.957 ;
     RECT  32.292 1.759 33.57 1.963 ;
     RECT  34.308 1.723 51.678 1.963 ;
     RECT  18.864 1.957 20.754 2.029 ;
     RECT  21.816 1.915 31.374 2.029 ;
     RECT  18.864 2.029 31.374 2.065 ;
     RECT  32.292 1.963 51.678 2.065 ;
     RECT  4.5 1.771 15.894 2.143 ;
     RECT  16.632 1.771 17.082 2.143 ;
     RECT  17.928 0.187 17.946 2.143 ;
     RECT  18.864 2.065 51.678 2.143 ;
     RECT  52.596 2.101 52.614 2.191 ;
     RECT  17.928 2.143 51.678 2.219 ;
     RECT  17.928 2.219 51.498 2.263 ;
     RECT  4.5 2.143 17.082 2.299 ;
     RECT  17.82 2.263 51.498 2.299 ;
     RECT  2.415 2.143 2.505 2.413 ;
     RECT  53.715 2.143 53.805 2.413 ;
     RECT  52.596 2.191 52.938 2.569 ;
     RECT  53.715 2.413 53.997 2.569 ;
     RECT  52.596 2.569 53.997 2.641 ;
     RECT  52.488 2.641 53.997 2.803 ;
     RECT  4.5 2.299 51.498 3.145 ;
     RECT  52.452 2.803 53.997 3.145 ;
     RECT  4.5 3.145 53.997 3.415 ;
     RECT  4.356 3.415 53.997 3.839 ;
     RECT  4.572 3.839 53.997 3.947 ;
     RECT  4.572 3.947 8.262 4.109 ;
     RECT  9 3.947 53.997 4.379 ;
     RECT  4.932 4.109 8.262 4.729 ;
     RECT  9 4.379 17.118 4.729 ;
     RECT  4.932 4.729 17.118 5.035 ;
     RECT  4.788 5.035 17.118 5.189 ;
     RECT  5.115 5.189 17.118 5.197 ;
     RECT  5.115 5.197 17.19 5.233 ;
     RECT  18.072 4.379 20.574 5.233 ;
     RECT  5.115 5.233 20.574 5.539 ;
     RECT  21.315 4.379 53.997 5.539 ;
     RECT  2.415 2.413 2.697 11.995 ;
     RECT  2.304 11.995 2.697 12.515 ;
     RECT  2.376 12.515 2.697 13.865 ;
     RECT  2.415 13.865 2.697 15.403 ;
     RECT  2.415 15.403 3.33 15.485 ;
     RECT  4.32 16.501 4.338 16.541 ;
     RECT  3.528 15.601 3.546 16.565 ;
     RECT  5.115 5.539 53.997 17.339 ;
     RECT  5.115 17.339 52.686 17.609 ;
     RECT  5.115 17.609 52.614 17.617 ;
     RECT  5.076 17.617 52.614 18.031 ;
     RECT  4.572 18.031 52.614 18.419 ;
     RECT  4.572 18.419 52.29 18.689 ;
     RECT  4.572 18.689 51.894 18.805 ;
     RECT  4.356 18.805 51.894 19.075 ;
     RECT  2.415 15.485 2.697 19.187 ;
     RECT  53.715 17.339 53.997 19.187 ;
     RECT  4.284 19.075 51.894 19.229 ;
     RECT  28.476 19.229 51.714 19.265 ;
     RECT  4.464 19.229 27.738 19.379 ;
     RECT  28.476 19.265 41.31 19.379 ;
     RECT  42.048 19.265 51.714 19.379 ;
     RECT  33.12 19.379 33.138 19.409 ;
     RECT  2.415 19.187 2.505 19.457 ;
     RECT  5.115 19.379 5.274 19.457 ;
     RECT  7.815 19.379 8.01 19.457 ;
     RECT  18.615 19.379 18.774 19.457 ;
     RECT  21.315 19.379 21.546 19.457 ;
     RECT  24.015 19.379 24.282 19.457 ;
     RECT  29.415 19.379 29.574 19.457 ;
     RECT  32.115 19.379 32.274 19.457 ;
     RECT  34.815 19.379 35.01 19.457 ;
     RECT  42.915 19.379 43.074 19.457 ;
     RECT  45 19.379 45.774 19.457 ;
     RECT  48.315 19.379 48.546 19.457 ;
     RECT  53.715 19.187 53.805 19.457 ;
     RECT  7.992 19.457 8.01 19.565 ;
     RECT  10.44 19.379 10.782 19.565 ;
     RECT  13.176 19.379 13.59 19.565 ;
     RECT  15.876 19.379 16.29 19.565 ;
     RECT  21.528 19.457 21.546 19.565 ;
     RECT  24.264 19.457 24.282 19.565 ;
     RECT  26.676 19.379 27.09 19.565 ;
     RECT  34.992 19.457 35.01 19.565 ;
     RECT  37.44 19.379 37.818 19.565 ;
     RECT  40.176 19.379 40.59 19.565 ;
     RECT  48.528 19.457 48.546 19.565 ;
     RECT  50.94 19.379 51.282 19.565 ;
     RECT  5.256 19.457 5.274 19.613 ;
     RECT  13.176 19.565 13.194 19.613 ;
     RECT  15.876 19.565 15.894 19.613 ;
     RECT  18.756 19.457 18.774 19.613 ;
     RECT  26.676 19.565 26.694 19.613 ;
     RECT  29.556 19.457 29.574 19.613 ;
     RECT  32.256 19.457 32.274 19.613 ;
     RECT  37.44 19.565 37.458 19.613 ;
     RECT  40.176 19.565 40.194 19.613 ;
     RECT  43.056 19.457 43.074 19.613 ;
     RECT  45.756 19.457 45.774 19.613 ;
     RECT  45 19.457 45.018 20.573 ;
     RECT  30.528 21.355 30.546 21.485 ;
    LAYER M4 ;
     RECT  0.156 10.8 0.227 10.824 ;
     RECT  0.181 12 2.408 12.024 ;
     RECT  2.408 2.148 2.512 19.452 ;
     RECT  2.512 2.418 2.704 19.182 ;
     RECT  2.704 14.112 2.819 14.136 ;
     RECT  2.704 15.408 3.341 15.432 ;
     RECT  4.268 16.512 4.309 16.536 ;
     RECT  4.46 1.104 4.645 1.128 ;
     RECT  4.645 0.192 4.805 1.128 ;
     RECT  4.309 16.512 4.957 17.4 ;
     RECT  4.805 0.192 5.108 1.752 ;
     RECT  4.957 16.512 5.108 18.168 ;
     RECT  4.453 19.344 5.108 19.368 ;
     RECT  5.108 0.192 5.173 19.452 ;
     RECT  5.173 0.192 5.285 19.608 ;
     RECT  5.285 0.192 5.404 19.368 ;
     RECT  5.404 0.192 5.761 1.8 ;
     RECT  5.761 0.576 6.221 1.8 ;
     RECT  6.221 0.576 6.545 0.6 ;
     RECT  6.221 1.728 6.677 1.8 ;
     RECT  6.677 1.728 7.237 1.848 ;
     RECT  6.893 0.192 7.541 0.216 ;
     RECT  7.237 1.728 7.541 2.184 ;
     RECT  7.541 0.192 7.625 2.184 ;
     RECT  7.625 1.728 7.808 2.184 ;
     RECT  7.669 5.76 7.808 5.784 ;
     RECT  5.404 17.04 7.808 18.168 ;
     RECT  5.404 19.344 7.808 19.368 ;
     RECT  7.808 1.728 7.957 19.452 ;
     RECT  7.957 1.728 8.044 19.56 ;
     RECT  8.044 1.728 8.104 19.368 ;
     RECT  7.625 0.192 8.165 0.6 ;
     RECT  8.104 5.76 8.165 5.784 ;
     RECT  8.165 0.576 8.345 0.6 ;
     RECT  8.104 17.136 8.525 18.168 ;
     RECT  8.104 1.728 9.157 1.848 ;
     RECT  9.157 1.152 9.565 1.848 ;
     RECT  8.525 17.376 9.685 18.168 ;
     RECT  8.104 19.344 9.685 19.368 ;
     RECT  9.565 1.152 9.893 2.28 ;
     RECT  9.685 17.376 10.405 19.368 ;
     RECT  9.893 1.728 10.508 2.28 ;
     RECT  10.357 5.76 10.508 5.784 ;
     RECT  10.357 16.32 10.508 16.344 ;
     RECT  10.405 17.376 10.508 19.56 ;
     RECT  10.508 1.728 10.804 19.56 ;
     RECT  10.804 16.32 10.828 19.56 ;
     RECT  10.828 16.32 11.045 19.368 ;
     RECT  10.804 6.816 11.189 6.84 ;
     RECT  10.804 5.76 11.405 5.784 ;
     RECT  10.804 1.728 11.411 2.28 ;
     RECT  11.045 16.32 11.941 18.168 ;
     RECT  11.029 0.576 11.945 0.6 ;
     RECT  11.941 16.032 11.981 18.168 ;
     RECT  11.411 1.728 11.996 1.8 ;
     RECT  11.893 5.136 12.421 5.16 ;
     RECT  11.996 0.864 12.556 1.8 ;
     RECT  12.556 0.864 12.757 1.848 ;
     RECT  12.757 0.864 12.913 2.328 ;
     RECT  10.804 3.456 12.913 4.152 ;
     RECT  11.045 19.344 13.141 19.368 ;
     RECT  12.913 0.864 13.208 4.152 ;
     RECT  12.421 5.136 13.208 5.256 ;
     RECT  12.265 6.288 13.208 6.312 ;
     RECT  11.981 16.032 13.208 16.056 ;
     RECT  11.981 17.088 13.208 18.168 ;
     RECT  13.141 19.344 13.208 19.608 ;
     RECT  13.208 0.864 13.228 19.608 ;
     RECT  13.228 0.864 13.237 19.56 ;
     RECT  13.237 0.288 13.504 19.56 ;
     RECT  13.504 0.288 13.525 3.144 ;
     RECT  13.504 17.088 13.612 19.56 ;
     RECT  13.525 0.192 13.667 3.144 ;
     RECT  13.612 17.088 14.213 19.368 ;
     RECT  13.504 4.128 14.609 6.312 ;
     RECT  14.609 5.712 14.641 6.312 ;
     RECT  14.641 5.712 14.825 7.224 ;
     RECT  13.667 0.864 15.157 3.144 ;
     RECT  15.157 0.816 15.493 3.144 ;
     RECT  14.213 19.344 15.865 19.368 ;
     RECT  15.493 0.192 15.908 3.144 ;
     RECT  14.609 4.128 15.908 4.68 ;
     RECT  14.825 5.712 15.908 6.312 ;
     RECT  13.504 16.032 15.908 16.056 ;
     RECT  14.213 17.088 15.908 18.168 ;
     RECT  15.865 19.344 15.908 19.608 ;
     RECT  15.908 0.192 15.925 19.608 ;
     RECT  15.925 0.096 15.971 19.608 ;
     RECT  15.971 0.096 16.204 19.56 ;
     RECT  16.204 19.344 16.307 19.56 ;
     RECT  16.204 17.088 16.739 18.168 ;
     RECT  16.739 17.376 17.561 18.168 ;
     RECT  17.561 17.376 18.565 17.496 ;
     RECT  16.204 0.096 18.608 6.072 ;
     RECT  16.204 16.032 18.608 16.056 ;
     RECT  18.565 17.376 18.608 18.168 ;
     RECT  16.307 19.344 18.608 19.368 ;
     RECT  18.608 0.096 18.709 19.452 ;
     RECT  18.709 0.096 18.796 19.608 ;
     RECT  18.796 0.096 18.904 19.368 ;
     RECT  18.904 0.096 20.149 5.208 ;
     RECT  20.149 0.096 20.221 5.544 ;
     RECT  20.221 0.048 20.293 5.544 ;
     RECT  18.904 17.376 21.268 18.168 ;
     RECT  20.293 0.048 21.308 6.36 ;
     RECT  18.904 16.032 21.308 16.056 ;
     RECT  21.268 17.376 21.308 18.216 ;
     RECT  18.904 19.344 21.308 19.368 ;
     RECT  21.308 0.048 21.493 19.452 ;
     RECT  21.493 0.048 21.58 19.56 ;
     RECT  21.58 0.048 21.604 19.368 ;
     RECT  21.604 17.376 22.789 18.216 ;
     RECT  21.604 19.344 22.789 19.368 ;
     RECT  21.604 0.048 23.173 6.36 ;
     RECT  21.604 7.632 23.173 7.656 ;
     RECT  21.604 16.032 23.281 16.056 ;
     RECT  23.281 16.032 23.569 16.344 ;
     RECT  22.789 17.376 23.569 19.368 ;
     RECT  23.173 0.048 24.008 7.656 ;
     RECT  23.569 16.032 24.008 19.368 ;
     RECT  24.008 0.048 24.229 19.452 ;
     RECT  24.229 0.048 24.304 19.56 ;
     RECT  24.304 16.32 24.316 19.56 ;
     RECT  24.316 16.32 24.653 19.368 ;
     RECT  24.304 0.048 24.689 7.656 ;
     RECT  24.689 0.048 26.377 5.592 ;
     RECT  24.689 6.864 26.377 7.656 ;
     RECT  24.653 16.608 26.636 19.368 ;
     RECT  26.377 0.048 26.708 7.656 ;
     RECT  26.636 16.608 26.708 19.608 ;
     RECT  26.708 0.048 26.723 19.608 ;
     RECT  26.723 0.048 27.004 19.56 ;
     RECT  27.004 16.848 27.101 19.56 ;
     RECT  27.101 16.848 27.857 17.4 ;
     RECT  27.857 17.088 28.073 17.4 ;
     RECT  27.101 18.816 28.501 19.368 ;
     RECT  28.073 17.088 29.185 17.112 ;
     RECT  28.501 18.144 29.185 19.368 ;
     RECT  27.004 0.048 29.408 7.656 ;
     RECT  29.185 17.088 29.408 19.368 ;
     RECT  29.408 0.048 29.461 19.452 ;
     RECT  29.461 0.048 29.585 19.608 ;
     RECT  29.585 0.048 29.704 19.368 ;
     RECT  30.469 21.36 30.517 21.384 ;
     RECT  30.517 21.36 30.557 21.48 ;
     RECT  30.557 21.456 30.601 21.48 ;
     RECT  29.704 0.048 32.108 7.656 ;
     RECT  29.704 16.944 32.108 19.368 ;
     RECT  32.108 0.048 32.197 19.452 ;
     RECT  32.197 0.048 32.285 19.608 ;
     RECT  32.285 0.048 32.404 19.368 ;
     RECT  32.404 0.048 32.825 7.656 ;
     RECT  32.404 16.848 32.825 19.368 ;
     RECT  32.825 5.424 33.185 7.656 ;
     RECT  32.825 0.048 33.203 4.248 ;
     RECT  32.825 17.04 33.829 19.368 ;
     RECT  33.829 16.896 33.937 19.368 ;
     RECT  33.203 0.096 34.445 4.248 ;
     RECT  34.445 0.192 34.808 4.248 ;
     RECT  33.185 5.472 34.808 7.656 ;
     RECT  33.937 16.656 34.808 19.368 ;
     RECT  34.808 0.192 34.94 19.452 ;
     RECT  34.94 0.192 35.027 19.56 ;
     RECT  35.027 0.192 35.104 19.368 ;
     RECT  35.104 0.192 35.404 4.248 ;
     RECT  35.404 0.288 35.705 4.248 ;
     RECT  35.104 16.512 35.929 17.976 ;
     RECT  35.705 0.288 36.227 3.432 ;
     RECT  36.227 0.48 36.397 3.432 ;
     RECT  36.397 0.48 36.497 2.904 ;
     RECT  36.497 0.48 36.899 2.568 ;
     RECT  35.104 19.344 37.388 19.368 ;
     RECT  37.388 19.344 37.475 19.608 ;
     RECT  36.899 0.816 37.508 2.568 ;
     RECT  37.141 3.936 37.508 3.96 ;
     RECT  35.104 5.472 37.508 5.496 ;
     RECT  35.104 7.632 37.508 7.656 ;
     RECT  35.929 16.608 37.508 17.976 ;
     RECT  37.475 19.344 37.508 19.56 ;
     RECT  37.508 0.816 37.804 19.56 ;
     RECT  37.804 19.344 37.852 19.56 ;
     RECT  37.804 0.816 38.113 3.48 ;
     RECT  38.113 0.576 38.771 3.48 ;
     RECT  37.804 6.096 39.017 6.12 ;
     RECT  37.852 19.344 40.124 19.368 ;
     RECT  38.771 0.576 40.208 2.856 ;
     RECT  37.804 7.632 40.208 7.656 ;
     RECT  37.804 16.608 40.208 18.168 ;
     RECT  40.124 19.344 40.208 19.608 ;
     RECT  40.208 0.576 40.211 19.608 ;
     RECT  40.211 0.576 40.489 19.56 ;
     RECT  40.489 0.192 40.504 19.56 ;
     RECT  40.504 19.344 40.636 19.56 ;
     RECT  40.504 5.184 40.637 5.208 ;
     RECT  40.504 2.88 41.171 4.008 ;
     RECT  41.171 2.88 41.363 3.912 ;
     RECT  40.636 19.344 41.557 19.368 ;
     RECT  41.363 3.888 41.609 3.912 ;
     RECT  41.557 18.816 41.644 19.368 ;
     RECT  40.504 0.192 42.325 1.752 ;
     RECT  41.605 2.832 42.325 2.856 ;
     RECT  42.325 0.192 42.581 2.856 ;
     RECT  42.581 1.392 42.617 2.856 ;
     RECT  40.504 16.608 42.757 17.64 ;
     RECT  41.644 19.344 42.865 19.368 ;
     RECT  42.581 0.192 42.899 0.312 ;
     RECT  42.617 1.68 42.908 2.856 ;
     RECT  42.793 4.224 42.908 4.248 ;
     RECT  42.757 16.512 42.908 17.64 ;
     RECT  42.865 18.768 42.908 19.368 ;
     RECT  42.908 1.68 42.949 19.452 ;
     RECT  42.949 1.68 43.085 19.608 ;
     RECT  43.085 1.68 43.204 19.368 ;
     RECT  42.899 0.192 43.265 0.216 ;
     RECT  43.204 3.984 43.427 4.536 ;
     RECT  43.204 1.68 43.763 1.752 ;
     RECT  43.427 4.512 43.955 4.536 ;
     RECT  44.017 0.528 44.125 0.552 ;
     RECT  43.204 16.608 44.165 19.368 ;
     RECT  44.125 0.528 44.291 1.128 ;
     RECT  44.291 0.528 44.341 0.6 ;
     RECT  44.341 0.48 44.435 0.6 ;
     RECT  43.204 2.88 44.485 2.904 ;
     RECT  44.557 3.984 44.641 4.008 ;
     RECT  44.165 16.608 44.809 17.688 ;
     RECT  44.972 20.544 45.059 20.568 ;
     RECT  44.485 2.208 45.133 2.904 ;
     RECT  44.435 0.528 45.457 0.6 ;
     RECT  45.133 1.68 45.529 2.904 ;
     RECT  45.457 0.48 45.589 0.6 ;
     RECT  45.529 1.68 45.589 3.432 ;
     RECT  45.589 0.48 45.608 3.432 ;
     RECT  44.809 16.368 45.608 17.688 ;
     RECT  44.165 19.344 45.608 19.368 ;
     RECT  45.608 0.48 45.733 19.452 ;
     RECT  45.733 0.48 45.82 19.608 ;
     RECT  45.82 0.48 45.904 19.368 ;
     RECT  45.904 0.48 45.925 1.752 ;
     RECT  45.904 3.408 46.067 3.96 ;
     RECT  45.904 16.368 46.217 17.112 ;
     RECT  45.925 0.192 46.499 1.752 ;
     RECT  46.499 1.68 46.691 1.752 ;
     RECT  45.904 18.528 46.757 19.368 ;
     RECT  46.217 16.8 46.793 17.112 ;
     RECT  46.793 16.848 46.897 17.112 ;
     RECT  46.499 0.192 47.045 0.216 ;
     RECT  47.149 2.832 47.185 2.856 ;
     RECT  46.067 3.936 47.219 3.96 ;
     RECT  46.691 1.728 48.013 1.752 ;
     RECT  48.013 1.632 48.308 1.752 ;
     RECT  47.185 2.736 48.308 2.856 ;
     RECT  46.897 16.848 48.308 18.024 ;
     RECT  46.757 19.344 48.308 19.368 ;
     RECT  48.308 1.632 48.419 19.452 ;
     RECT  48.419 2.256 48.476 19.452 ;
     RECT  47.761 0.528 48.517 0.552 ;
     RECT  48.476 2.256 48.563 19.56 ;
     RECT  48.563 2.256 48.604 19.368 ;
     RECT  48.604 16.848 48.665 18.168 ;
     RECT  48.517 0.192 48.689 0.552 ;
     RECT  48.689 0.192 48.809 0.6 ;
     RECT  48.809 0.24 48.925 0.6 ;
     RECT  48.925 0.576 49.045 0.6 ;
     RECT  49.045 0.576 49.381 1.176 ;
     RECT  48.604 2.256 49.381 2.28 ;
     RECT  49.381 0.576 49.637 2.28 ;
     RECT  49.637 1.152 49.763 2.28 ;
     RECT  49.763 1.152 50.501 1.752 ;
     RECT  48.665 16.848 50.713 18.024 ;
     RECT  48.604 19.344 50.917 19.368 ;
     RECT  50.501 1.728 50.965 1.752 ;
     RECT  50.885 0.576 50.969 0.6 ;
     RECT  50.965 1.728 51.008 1.8 ;
     RECT  50.533 14.832 51.008 14.856 ;
     RECT  50.713 16.848 51.008 18.264 ;
     RECT  50.917 19.344 51.008 19.56 ;
     RECT  51.008 1.728 51.299 19.56 ;
     RECT  51.299 1.728 51.304 19.368 ;
     RECT  51.304 17.424 51.401 18.264 ;
     RECT  51.304 1.728 51.689 1.752 ;
     RECT  51.304 19.344 51.725 19.368 ;
     RECT  51.401 17.424 51.833 17.448 ;
     RECT  53.708 2.148 53.812 19.452 ;
     RECT  53.812 2.418 54.004 19.182 ;
    LAYER M5 ;
     RECT  15.936 0.085 15.96 0.144 ;
     RECT  33.168 0.037 33.192 0.144 ;
     RECT  34.368 0.133 34.392 0.144 ;
     RECT  4.512 0.144 51.672 0.275 ;
     RECT  35.136 0.275 51.672 0.371 ;
     RECT  4.512 0.275 34.056 0.419 ;
     RECT  4.512 0.419 33.768 1.139 ;
     RECT  4.848 1.139 33.768 1.427 ;
     RECT  18.24 1.427 22.92 1.475 ;
     RECT  18.24 1.475 22.728 1.523 ;
     RECT  22.704 1.523 22.728 1.571 ;
     RECT  4.848 1.427 17.064 1.763 ;
     RECT  35.472 0.371 51.672 1.763 ;
     RECT  5.1 1.763 17.064 1.811 ;
     RECT  6.72 1.811 14.664 1.859 ;
     RECT  24 1.427 33.768 1.907 ;
     RECT  35.472 1.763 41.688 2.137 ;
     RECT  2.4 2.137 2.52 2.151 ;
     RECT  53.7 2.137 53.82 2.151 ;
     RECT  7.248 1.859 8.112 2.195 ;
     RECT  9.648 1.859 14.328 2.291 ;
     RECT  47.184 1.763 49.752 2.291 ;
     RECT  34.8 2.137 41.688 2.867 ;
     RECT  42.768 1.763 46.056 2.867 ;
     RECT  47.184 2.291 48.612 2.867 ;
     RECT  24 1.907 33.432 2.915 ;
     RECT  18.24 1.523 21.72 3.059 ;
     RECT  28.176 2.915 33.432 3.059 ;
     RECT  18.24 3.059 19.128 3.107 ;
     RECT  24 2.915 27.012 3.107 ;
     RECT  18.6 3.107 19.128 3.395 ;
     RECT  28.176 3.059 30.888 3.443 ;
     RECT  34.8 2.867 38.76 3.443 ;
     RECT  40.2 2.867 41.352 3.443 ;
     RECT  45.6 2.867 46.056 3.443 ;
     RECT  37.2 3.443 38.76 3.491 ;
     RECT  24 3.107 25.32 3.731 ;
     RECT  29.4 3.443 30.888 3.971 ;
     RECT  37.2 3.491 37.812 3.971 ;
     RECT  47.184 2.867 47.208 3.971 ;
     RECT  31.872 3.059 33.432 4.019 ;
     RECT  40.2 3.443 41.16 4.019 ;
     RECT  42.9 2.867 44.616 4.019 ;
     RECT  42.9 4.019 43.944 4.547 ;
     RECT  30.864 3.971 30.888 4.595 ;
     RECT  32.1 4.019 33.432 4.691 ;
     RECT  11.904 2.291 14.328 5.171 ;
     RECT  15.9 1.811 17.064 5.219 ;
     RECT  12.432 5.171 14.328 5.267 ;
     RECT  25.296 3.731 25.32 5.507 ;
     RECT  20.16 3.059 21.72 5.555 ;
     RECT  13.2 5.267 14.328 5.747 ;
     RECT  7.68 2.195 8.112 5.795 ;
     RECT  10.368 2.291 10.812 5.795 ;
     RECT  20.976 5.555 21.72 6.323 ;
     RECT  33.408 4.691 33.432 6.899 ;
     RECT  21.3 6.323 21.72 7.667 ;
     RECT  0.192 10.789 0.216 12.035 ;
     RECT  2.4 2.151 2.712 14.101 ;
     RECT  2.4 14.101 2.808 15.443 ;
     RECT  10.5 5.795 10.812 16.309 ;
     RECT  24 3.731 24.312 16.309 ;
     RECT  5.1 1.811 5.412 16.501 ;
     RECT  34.8 3.443 35.112 16.501 ;
     RECT  42.9 4.547 43.212 16.501 ;
     RECT  34.8 16.501 35.88 16.885 ;
     RECT  24 16.309 24.552 17.029 ;
     RECT  15.9 5.219 16.212 17.077 ;
     RECT  23.616 17.029 24.552 17.077 ;
     RECT  45.6 3.443 45.912 17.077 ;
     RECT  4.32 16.501 5.412 17.411 ;
     RECT  15.9 17.077 16.728 17.411 ;
     RECT  42.768 16.501 43.212 17.603 ;
     RECT  33.84 16.885 35.88 17.987 ;
     RECT  10.368 16.309 10.812 18.037 ;
     RECT  13.2 5.747 13.512 18.133 ;
     RECT  23.616 17.077 24.84 18.181 ;
     RECT  29.4 3.971 29.712 18.709 ;
     RECT  28.176 3.443 28.2 18.805 ;
     RECT  5.1 17.411 5.412 19.333 ;
     RECT  7.8 5.795 8.112 19.333 ;
     RECT  9.696 18.037 10.812 19.333 ;
     RECT  13.2 18.133 14.184 19.333 ;
     RECT  15.9 17.411 16.212 19.333 ;
     RECT  18.6 3.395 18.912 19.333 ;
     RECT  21.3 7.667 21.612 19.333 ;
     RECT  22.8 18.181 24.84 19.333 ;
     RECT  26.7 3.107 27.012 19.333 ;
     RECT  28.08 18.805 28.2 19.333 ;
     RECT  29.4 18.709 30.552 19.333 ;
     RECT  32.1 4.691 32.412 19.333 ;
     RECT  33.84 17.987 35.112 19.333 ;
     RECT  37.5 3.971 37.812 19.333 ;
     RECT  40.2 4.019 40.512 19.333 ;
     RECT  41.568 18.805 41.592 19.333 ;
     RECT  42.9 17.603 43.212 19.333 ;
     RECT  45.6 17.077 46.008 19.333 ;
     RECT  48.3 2.867 48.612 19.333 ;
     RECT  51 1.763 51.312 19.333 ;
     RECT  2.4 15.443 2.712 19.449 ;
     RECT  53.7 2.151 54.012 19.449 ;
     RECT  2.4 19.449 2.52 19.463 ;
     RECT  53.7 19.449 53.82 19.463 ;
     RECT  4.512 19.333 51.672 21.456 ;
     RECT  30.528 21.456 30.552 21.491 ;
  END
END hbfd_rly_136_NS_fc_f2
END LIBRARY
